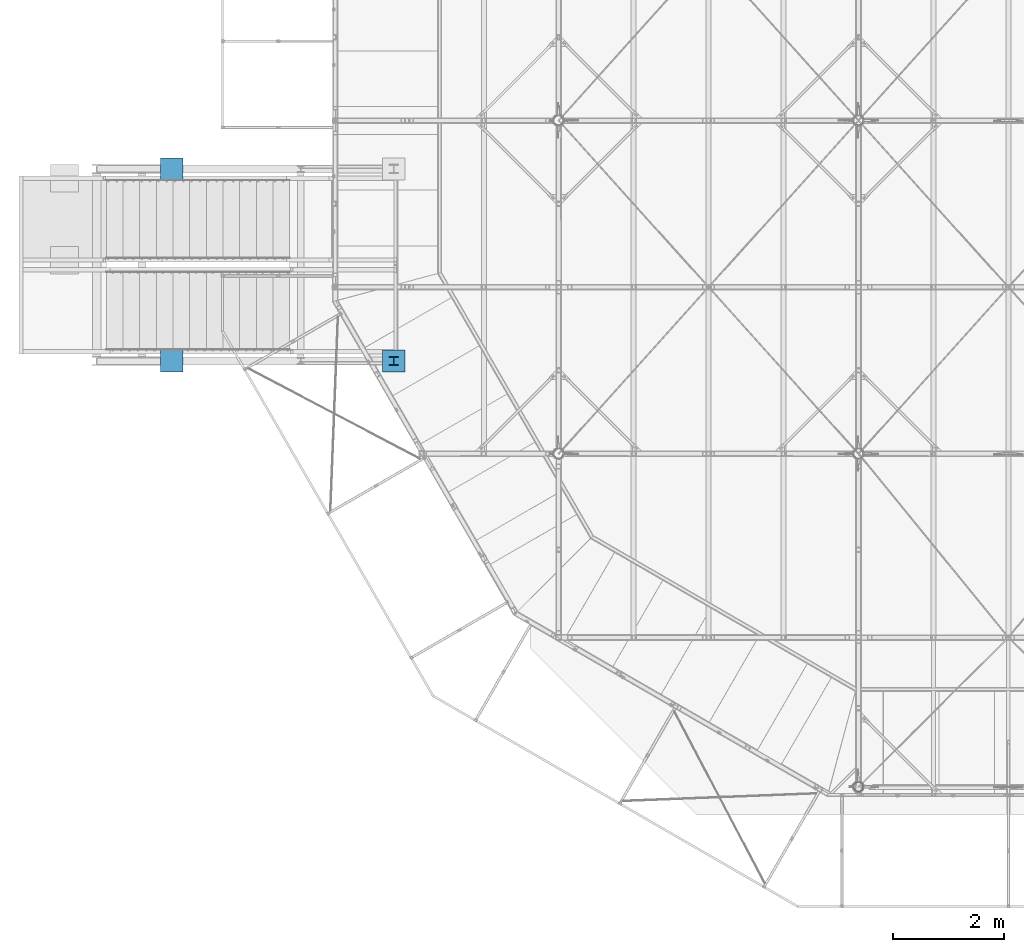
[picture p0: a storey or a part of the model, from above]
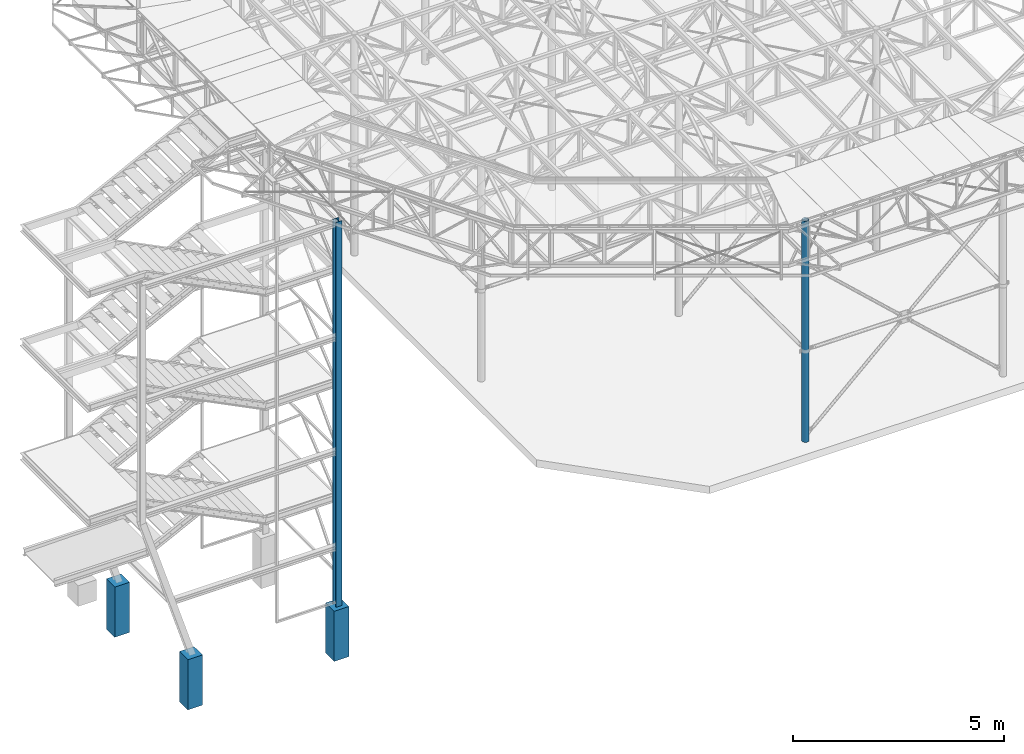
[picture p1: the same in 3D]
Properties of the parts of a building model (IFC2X3), part 1 of 2

# File
Description: ViewDefinition[CoordinationView_V2.0, QuantityTakeOffAddOnView], Option [BaseQuantities:On], Option [GridExport:On], Option [Assemblies:On], Option [Bolts:On], Option [Rebars:On], Option [PourObjects:Off], Option [Welds:Off], Option [SurfaceTreatments:Off], Option [LocationBy:0], Option [ViewColors:Off], Option [SectionedSpine:Off], Option [PropertySets:On], Option [Export all:On]
File name: IR_026-25_ifc_wzmocnienia_lądowiska.ifc
Time: 2025-10-02T10:39:26
Author: INFRARED\aneta.moskala
Organization: Structural Designer
Written by: IFC Database Version: Work
Made in: Tekla Structures Educational 2018, IFC Export Version: 4.0.0.0 Mar 15 2018

# IfcSite, Budowa
RefElevation: 0 mm

# IfcBuildingStorey, Undefined
In: Undefined
Elevation: 0 mm

# IfcBeam: BL8*100 (32)
In: Undefined
Description: BL8*100; Material: STEEL/S235JR
Tekla Common - Bottom elevation: +10.066; Top elevation: +10.166; Phase: 4; Class: 12
Tekla Quantity - Volume: 0 m3; Gross footprint area: 0 m2; Net surface area: 0.1 m2; Height: 100 mm; Width: 8 mm
Pset_BeamCommon - LoadBearing: no
Name | Weight (kg) | Area per tons (m2) | Tekla Quantity, Length (mm) | Reference | BaseQuantities, Length (mm) | OuterSurfaceArea (m2) | NetVolume (m3) | NetWeight (kg)
4 x BEAM | 3 | 35 | 479 | St10 | 479.039 | 0.104985 | 0.000382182 | 3.00013
12 x BEAM | 2.5 | 35.1 | 404 | s4 | 404.039 | 0.0887853 | 0.000322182 | 2.52913
6 x BEAM | 3.5 | 34.9 | 554 | s7 | 554.039 | 0.121185 | 0.000442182 | 3.47113
6 x BEAM | 3 | 35 | 479 | s5 | 479.039 | 0.104985 | 0.000382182 | 3.00013
4 x BEAM | 2.5 | 35.1 | 404 | St7 | 404.039 | 0.0887853 | 0.000322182 | 2.52913

# IfcBeam: C70*40*4 (34)
In: Undefined
Description: C70*40*4; Material: STEEL/S235
Tekla Common - Phase: 4; Class: 11
Tekla Quantity - Volume: 0 m3; Height: 70 mm; Width: 40 mm
Pset_BeamCommon - LoadBearing: no
Name | Bottom elevation | Top elevation | Weight (kg) | Gross footprint area (m2) | Area per tons (m2) | Net surface area (m2) | Tekla Quantity, Length (mm) | Reference | BaseQuantities, Length (mm) | OuterSurfaceArea (m2) | NetVolume (m3) | NetWeight (kg)
BEAM | +13.910 | +13.980 | 3.8 | 0 | 65.7 | 0.4 | 863 | k71 | 862.953 | 0.252133 | 0.000488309 | 3.83323
BEAM | +13.910 | +13.980 | 3.5 | 0 | 65.7 | 0.2 | 771.7 | k72 | 771.695 | 0.225485 | 0.000436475 | 3.42633
BEAM | +13.910 | +13.980 | 4.3 | 0 | 65.7 | 0.4 | 973 | k74 | 972.996 | 0.284266 | 0.000550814 | 4.32389
BEAM | +13.910 | +13.980 | 3.5 | 0 | 65.7 | 0.2 | 773 | k69 | 773.009 | 0.225869 | 0.000437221 | 3.43219
BEAM | +13.910 | +13.980 | 3.5 | 0 | 65.7 | 0.2 | 771.8 | k72 | 771.782 | 0.225511 | 0.000436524 | 3.42672
BEAM | +13.910 | +13.980 | 3.5 | 0 | 65.7 | 0.2 | 774.7 | k73 | 774.742 | 0.226375 | 0.000438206 | 3.43992
BEAM | +13.910 | +13.980 | 3.8 | 0 | 65.7 | 0.4 | 863 | k71 | 862.922 | 0.252124 | 0.000488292 | 3.83309
20 x BEAM | +13.910 | +13.980 | 13.2 | 0.1 | 65.7 | 0.8 | 2950 | K6 | 2950 | 0.862536 | 0.0016756 | 13.1535
2 x BEAM | +13.910 | +13.980 | 3.5 | 0 | 65.7 | 0.2 | 773 | k69 | 772.888 | 0.225834 | 0.000437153 | 3.43165
2 x BEAM | +13.910 | +13.980 | 3 | 0 | 65.9 | 0.2 | 683.7 | k70 | 683.709 | 0.199794 | 0.000386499 | 3.03402
BEAM | +13.911 | +13.981 | 12.1 | 0.1 | 65.7 | 0.8 | 2703.9 | K36 | 2703.9 | 0.790676 | 0.00153582 | 12.0562
BEAM | +13.910 | +13.980 | 6.8 | 0.1 | 65.7 | 0.4 | 1520 | K3 | 1520 | 0.444976 | 0.00086336 | 6.77738
BEAM | +13.910 | +13.980 | 6.7 | 0.1 | 65.7 | 0.4 | 1505 | K2 | 1505 | 0.440596 | 0.00085484 | 6.71049

# IfcBeam: CHS88.9*3 (23)
In: Undefined
Description: CHS88.9*3; Material: STEEL/S235JR
Tekla Common - Bottom elevation: +10.072; Top elevation: +10.160; Phase: 4; Class: 9
Tekla Quantity - Volume: 0 m3; Gross footprint area: 0 m2; Area per tons: 44.9 m2; Net surface area: 1.4 m2; Height: 88.9 mm; Width: 88.9 mm
Pset_BeamCommon - LoadBearing: no
Name | Weight (kg) | Tekla Quantity, Length (mm) | Reference | BaseQuantities, Length (mm) | OuterSurfaceArea (m2) | NetVolume (m3) | NetWeight (kg)
11 x BEAM | 30.2 | 4893.7 | s2 | 4893.73 | 1.35623 | 0.00384995 | 30.2221
12 x BEAM | 34.5 | 5584.2 | s6 | 5584.18 | 1.54783 | 0.00439468 | 34.4982

# IfcBeam: D10 (16)
In: Undefined
Description: D10; Material: STEEL/S235
Tekla Common - Top elevation: +13.951; Phase: 4; Class: 5
Tekla Quantity - Weight: 1.9 kg; Volume: 0 m3; Gross footprint area: 0 m2; Area per tons: 55.2 m2; Net surface area: 0.1 m2; Height: 10 mm; Width: 10 mm; Length: 3489 mm
Pset_BeamCommon - LoadBearing: no; Reference: B5
BaseQuantities - Length: 3489.02 mm; OuterSurfaceArea: 0.106957 m2; NetVolume: 0.000246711 m3; NetWeight: 1.93668 kg
Name | Bottom elevation
15 x BEAM | +13.848
BEAM | +13.847

# IfcBeam: D16 (32)
In: Undefined
Description: D16; Material: STEEL/S235
Tekla Common - Bottom elevation: +12.772; Top elevation: +12.788; Phase: 4; Class: 5
Tekla Quantity - Volume: 0 m3; Gross footprint area: 0 m2; Area per tons: 33 m2; Net surface area: 0.2 m2; Height: 16 mm; Width: 16 mm
Pset_BeamCommon - LoadBearing: no
Name | Weight (kg) | Tekla Quantity, Length (mm) | Reference | BaseQuantities, Length (mm) | OuterSurfaceArea (m2) | NetVolume (m3) | NetWeight (kg)
24 x BEAM | 6.1 | 4036.1 | K21 | 4036.09 | 0.20095 | 0.000774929 | 6.08319
4 x BEAM | 6.4 | 4271.5 | K27 | 4271.55 | 0.212651 | 0.000820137 | 6.43807
4 x BEAM | 5.7 | 3811.3 | K26 | 3811.31 | 0.189781 | 0.000731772 | 5.74441

# IfcBeam: HEB140, COLUMN
In: Undefined
Description: HEB140; Material: STEEL/S235
Tekla Common - Bottom elevation: +2.640; Top elevation: +2.780; Phase: 2; Class: 4
Tekla Quantity - Weight: 111.4 kg; Volume: 0 m3; Gross footprint area: 0.4 m2; Area per tons: 23.8 m2; Net surface area: 2.7 m2; Height: 140 mm; Width: 140 mm; Length: 3300 mm
Pset_BeamCommon - LoadBearing: no; Reference: S3
BaseQuantities - Length: 3300 mm; OuterSurfaceArea: 2.6565 m2; NetVolume: 0.0137676 m3; NetWeight: 108.076 kg

# IfcBeam: HEB160 (3)
In: Undefined
Description: HEB160; Material: STEEL/S235
Tekla Common - Phase: 2; Class: 4
Tekla Quantity - Weight: 140.7 kg; Volume: 0 m3; Gross footprint area: 0.4 m2; Area per tons: 21.5 m2; Net surface area: 3.1 m2; Height: 160 mm; Width: 160 mm; Length: 3300 mm
Pset_BeamCommon - LoadBearing: no; Reference: S2
BaseQuantities - Length: 3300 mm; OuterSurfaceArea: 3.0294 m2; NetVolume: 0.0172656 m3; NetWeight: 135.535 kg
Name | Bottom elevation | Top elevation
COLUMN | +11.990 | +12.150
COLUMN | +8.690 | +8.850
COLUMN | +5.390 | +5.550

# IfcBeam: IPE120 (6)
In: Undefined
Description: IPE120; Material: STEEL/S235
Tekla Common - Bottom elevation: +13.760; Top elevation: +13.880; Phase: 4; Class: 5
Tekla Quantity - Weight: 28.5 kg; Volume: 0 m3; Gross footprint area: 0.2 m2; Area per tons: 45.8 m2; Net surface area: 1.3 m2; Height: 120 mm; Width: 64 mm
Pset_BeamCommon - LoadBearing: no
Name | Tekla Quantity, Length (mm) = BaseQuantities, Length (mm) | Reference | OuterSurfaceArea (m2) | NetVolume (m3) | NetWeight (kg)
2 x BEAM | 2753.9 | B8 | 1.3081 | 0.00352213 | 27.6487
2 x BEAM | 2754.9 | B8 | 1.30858 | 0.00352341 | 27.6587
BEAM | 2753.9 | k79 | 1.3081 | 0.00352213 | 27.6487
BEAM | 2754.9 | k79 | 1.30858 | 0.00352341 | 27.6587

# IfcBeam: IPE180 (64)
In: Undefined
Description: IPE180; Material: STEEL/S235
Tekla Common - Bottom elevation: +13.700; Top elevation: +13.880; Phase: 4; Class: 5
Tekla Quantity - Volume: 0 m3; Gross footprint area: 0.4 m2; Area per tons: 37.2 m2; Height: 180 mm; Width: 91 mm
Pset_BeamCommon - LoadBearing: no
Name | Weight (kg) | Net surface area (m2) | Tekla Quantity, Length (mm) = BaseQuantities, Length (mm) | Reference | OuterSurfaceArea (m2) | NetVolume (m3) | NetWeight (kg)
46 x BEAM | 54.4 | 2.1 | 2900 | B6 | 2.0242 | 0.00674308 | 52.9332
9 x BEAM | 60.2 | 2.3 | 3210 | B7 | 2.24058 | 0.00746389 | 58.5916
9 x BEAM | 60.2 | 2.3 | 3211 | B7 | 2.24128 | 0.00746622 | 58.6098

# IfcBeam: L150*75*9, BEAM
In: Undefined
Description: L150*75*9; Material: STEEL/S235
Tekla Common - Bottom elevation: +13.880; Top elevation: +14.030; Phase: 4; Class: 5
Tekla Quantity - Weight: 84.4 kg; Volume: 0 m3; Gross footprint area: 0 m2; Area per tons: 28.8 m2; Net surface area: 2.4 m2; Height: 150 mm; Width: 75 mm; Length: 5511.2 mm
Pset_BeamCommon - LoadBearing: no; Reference: k82
BaseQuantities - Length: 5511.18 mm; OuterSurfaceArea: 2.43043 m2; NetVolume: 0.0106522 m3; NetWeight: 83.6199 kg

# IfcBeam: L60*40*6, BEAM
In: Undefined
Description: L60*40*6; Material: STEEL/S235
Tekla Common - Bottom elevation: +13.984; Top elevation: +14.024; Phase: 4; Class: 5
Tekla Quantity - Weight: 29.1 kg; Volume: 0 m3; Gross footprint area: 0 m2; Area per tons: 43.7 m2; Net surface area: 1.3 m2; Height: 60 mm; Width: 40 mm; Length: 6524.9 mm
Pset_BeamCommon - LoadBearing: no; Reference: k92
BaseQuantities - Length: 6524.86 mm; OuterSurfaceArea: 1.27235 m2; NetVolume: 0.0036739 m3; NetWeight: 28.8401 kg

# IfcBeam: RHS100*60*6 (2)
In: Undefined
Description: RHS100*60*6; Material: STEEL/S235
Tekla Common - Bottom elevation: +13.780; Top elevation: +13.880; Phase: 4; Class: 11
Tekla Quantity - Weight: 89.6 kg; Volume: 0 m3; Gross footprint area: 0.4 m2; Area per tons: 22.6 m2; Net surface area: 2 m2; Height: 100 mm; Width: 60 mm; Length: 6524 mm
Pset_BeamCommon - LoadBearing: no; Reference: k25
BaseQuantities - Length: 6524 mm; OuterSurfaceArea: 2.02768 m2; NetVolume: 0.011416 m3; NetWeight: 89.6155 kg

# IfcBeam: RHS60*40*6 (77)
In: Undefined
Description: RHS60*40*6; Material: STEEL/S235
Tekla Common - Bottom elevation: +13.880; Top elevation: +13.984; Phase: 4; Class: 5
Tekla Quantity - Weight: 0.8 kg; Volume: 0 m3; Gross footprint area: 0 m2; Area per tons: 25 m2; Net surface area: 0 m2; Height: 60 mm; Width: 40 mm
Pset_BeamCommon - LoadBearing: no; Reference: B4
Name | Tekla Quantity, Length (mm) | BaseQuantities, Length (mm) | OuterSurfaceArea (m2) | NetVolume (m3) | NetWeight (kg)
28 x BEAM | 103.6 | 103.598 | 0.0214324 | 0.000109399 | 0.858784
28 x BEAM | 104 | 103.989 | 0.0215089 | 0.000109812 | 0.862027
7 x BEAM | 104 | 103.986 | 0.0215084 | 0.000109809 | 0.862003
14 x BEAM | 104 | 103.938 | 0.021499 | 0.000109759 | 0.861604

# IfcBeam: SHS100*5 (4)
In: Undefined
Description: SHS100*5; Material: STEEL/S235
Tekla Common - Bottom elevation: +13.780; Top elevation: +13.880; Phase: 4; Class: 11
Tekla Quantity - Weight: 48.7 kg; Volume: 0 m3; Gross footprint area: 0.4 m2; Area per tons: 26.9 m2; Net surface area: 1.3 m2; Height: 100 mm; Width: 100 mm; Length: 3305.6 mm
Pset_BeamCommon - LoadBearing: no; Reference: k36
BaseQuantities - Length: 3305.58 mm; OuterSurfaceArea: 1.30752 m2; NetVolume: 0.0062003 m3; NetWeight: 48.6724 kg

# IfcBeam: SHS100*8 (51)
In: Undefined
Description: SHS100*8; Material: STEEL/S235
Tekla Quantity - Volume: 0 m3; Height: 100 mm; Width: 100 mm
Tekla Common - Bottom elevation: +13.780; Top elevation: +13.880; Phase: 4; Class: 11
Pset_BeamCommon - LoadBearing: no
Name | Weight (kg) | Gross footprint area (m2) | Area per tons (m2) | Net surface area (m2) | Tekla Quantity, Length (mm) | Reference | BaseQuantities, Length (mm) | OuterSurfaceArea (m2) | NetVolume (m3) | NetWeight (kg)
4 x BEAM | 67 | 0.4 | 17.4 | 1.3 | 2900 | k46 | 2900 | 1.1632 | 0.0085376 | 67.0202
4 x BEAM | 4.7 | 0 | 18 | 0.1 | 212.3 | k44 | 212.282 | 0.0828103 | 0.000585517 | 4.59631
4 x BEAM | 56.4 | 0.2 | 17.4 | 1 | 2448.9 | k23 | 2448.92 | 0.980265 | 0.00718892 | 56.433
4 x BEAM | 93 | 0.4 | 17.3 | 1.6 | 4025 | k22 | 4025 | 1.6132 | 0.0118496 | 93.0194
2 x BEAM | 92.3 | 0.4 | 17.3 | 1.6 | 4000.9 | k19 | 4000.92 | 1.60107 | 0.011758 | 92.3004
12 x BEAM | 122.5 | 0.4 | 17.3 | 2.1 | 5300 | k9 | 5300 | 2.1232 | 0.0156032 | 122.485
4 x BEAM | 75.8 | 0.4 | 17.4 | 1.3 | 3286 | k11 | 3286.02 | 1.31511 | 0.00965334 | 75.7787
8 x BEAM | 134.9 | 0.7 | 17.3 | 2.3 | 5852 | k6 | 5852.04 | 2.33901 | 0.017187 | 134.918
9 x BEAM | 121.1 | 0.4 | 17.3 | 2.1 | 5252 | k2 | 5252.04 | 2.09901 | 0.0154206 | 121.052

# IfcBeam: SHS50*5 (36)
In: Undefined
Description: SHS50*5; Material: STEEL/S235
Tekla Common - Bottom elevation: +12.805; Top elevation: +12.855; Phase: 4; Class: 11
Tekla Quantity - Weight: 12 kg; Volume: 0 m3; Gross footprint area: 0.1 m2; Area per tons: 28.5 m2; Net surface area: 0.4 m2; Height: 50 mm; Width: 50 mm
Pset_BeamCommon - LoadBearing: no; Reference: k48
Name | Tekla Quantity, Length (mm) | BaseQuantities, Length (mm) | OuterSurfaceArea (m2) | NetVolume (m3) | NetWeight (kg)
18 x BEAM | 1700.3 | 1700.3 | 0.34106 | 0.00153027 | 12.0126
18 x BEAM | 1700 | 1700.02 | 0.341004 | 0.00153002 | 12.0106

# IfcBeam: SHS60*4 (10)
In: Undefined
Description: SHS60*4; Material: STEEL/S235
Tekla Common - Phase: 2; Class: 4
Tekla Quantity - Volume: 0 m3; Area per tons: 34.2 m2; Height: 60 mm; Width: 60 mm
Pset_BeamCommon - LoadBearing: no
Name | Bottom elevation | Top elevation | Weight (kg) | Gross footprint area (m2) | Net surface area (m2) | Tekla Quantity, Length (mm) = BaseQuantities, Length (mm) | Reference | OuterSurfaceArea (m2) | NetVolume (m3) | NetWeight (kg)
2 x BEAM | +2.780 | +5.400 | 18.4 | 0 | 0.6 | 2620 | B1 | 0.62976 | 0.00234752 | 18.428
2 x BEAM | +8.840 | +12.000 | 22.2 | 0 | 0.8 | 3160 | B2 | 0.75936 | 0.00283136 | 22.2262
2 x BEAM | +5.540 | +8.700 | 22.2 | 0 | 0.8 | 3160 | B2 | 0.75936 | 0.00283136 | 22.2262
COLUMN | +12.040 | +12.100 | 23.2 | 0.2 | 0.8 | 3300 | k100 | 0.79296 | 0.0029568 | 23.2109
COLUMN | +8.740 | +8.800 | 23.2 | 0.2 | 0.8 | 3300 | k100 | 0.79296 | 0.0029568 | 23.2109
COLUMN | +5.440 | +5.500 | 23.2 | 0.2 | 0.8 | 3300 | k100 | 0.79296 | 0.0029568 | 23.2109
COLUMN | +1.880 | +1.940 | 23.2 | 0.2 | 0.8 | 3300 | S7 | 0.79296 | 0.0029568 | 23.2109

# IfcBeam: UPE200 (3)
In: Undefined
Description: UPE200; Material: STEEL/S235
Tekla Common - Phase: 2; Class: 4
Tekla Quantity - Weight: 81.6 kg; Volume: 0 m3; Gross footprint area: 0.4 m2; Area per tons: 27.9 m2; Net surface area: 2.3 m2; Height: 200 mm; Width: 80 mm; Length: 3300 mm
Pset_BeamCommon - LoadBearing: no; Reference: k99
BaseQuantities - Length: 3300 mm; OuterSurfaceArea: 2.277 m2; NetVolume: 0.0102135 m3; NetWeight: 80.176 kg
Name | Bottom elevation | Top elevation
COLUMN | +10.500 | +10.700
COLUMN | +7.200 | +7.400
COLUMN | +3.900 | +4.100

# IfcBeam: UPN200 (3)
In: Undefined
Description: UPN200; Material: STEEL/S235
Tekla Common - Phase: 2; Class: 3
Tekla Quantity - Weight: 80.9 kg; Volume: 0 m3; Gross footprint area: 0.2 m2; Area per tons: 26.1 m2; Net surface area: 2.2 m2; Height: 200 mm; Width: 75 mm; Length: 3200 mm
Pset_BeamCommon - LoadBearing: no; Reference: A1
BaseQuantities - Length: 3200 mm; OuterSurfaceArea: 2.112 m2; NetVolume: 0.0103344 m3; NetWeight: 81.125 kg
Name | Bottom elevation | Top elevation
BELKA | +12.150 | +12.350
BELKA | +8.850 | +9.050
BELKA | +5.550 | +5.750

# IfcColumn: 400*400 (4)
In: Undefined
Description: 400*400; Material: CONCRETE/C25/30
Tekla Common - Bottom elevation: -0.430; Top elevation: +1.020; Phase: 2; Class: 13
Tekla Quantity - Weight: 556.8 kg; Volume: 0.2 m3; Gross footprint area: 0.2 m2; Area per tons: 4.7 m2; Net surface area: 2.6 m2; Height: 400 mm; Width: 400 mm; Length: 1450 mm
Pset_ColumnCommon - LoadBearing: yes; Reference: S4
BaseQuantities - Length: 1450 mm; OuterSurfaceArea: 2.64 m2; NetVolume: 0.232 m3; NetWeight: 556.8 kg

# IfcColumn: 500*500 (2)
In: Undefined
Description: 500*500; Material: CONCRETE/C25/30
Tekla Common - Bottom elevation: +2.180; Top elevation: +2.780; Phase: 2; Class: 13
Tekla Quantity - Weight: 360 kg; Volume: 0.2 m3; Gross footprint area: 0.4 m2; Area per tons: 4.7 m2; Net surface area: 1.7 m2; Height: 500 mm; Width: 500 mm; Length: 600 mm
Pset_ColumnCommon - LoadBearing: yes; Reference: S1
BaseQuantities - Length: 600 mm; OuterSurfaceArea: 1.7 m2; NetVolume: 0.15 m3; NetWeight: 360 kg

# IfcColumn: CHS177.8*12.5 (16)
In: Undefined
Description: CHS177.8*12.5; Material: STEEL/S235
Tekla Common - Bottom elevation: +7.491; Top elevation: +13.880; Phase: 4; Class: 4
Tekla Quantity - Weight: 321.9 kg; Volume: 0 m3; Gross footprint area: 0 m2; Area per tons: 11.1 m2; Net surface area: 3.6 m2; Height: 177.8 mm; Width: 177.8 mm; Length: 6389 mm
Pset_ColumnCommon - LoadBearing: no
BaseQuantities - Length: 6389 mm; OuterSurfaceArea: 3.56546 m2; NetVolume: 0.0410009 m3; NetWeight: 321.857 kg
Name | Reference
14 x COLUMN | k1
2 x COLUMN | S12

# IfcColumn: HEB120, BEAM
In: Undefined
Description: HEB120; Material: STEEL/S235
Tekla Common - Bottom elevation: +12.140; Top elevation: +13.800; Phase: 2; Class: 4
Tekla Quantity - Weight: 44.3 kg; Volume: 0 m3; Gross footprint area: 0 m2; Area per tons: 25.7 m2; Net surface area: 1.3 m2; Height: 120 mm; Width: 120 mm; Length: 1660 mm
Pset_ColumnCommon - LoadBearing: no; Reference: k127
BaseQuantities - Length: 1660 mm; OuterSurfaceArea: 1.13876 m2; NetVolume: 0.00543982 m3; NetWeight: 42.7026 kg

# IfcColumn: HEB160 (2)
In: Undefined
Description: HEB160; Material: STEEL/S235
Tekla Common - Bottom elevation: +1.020; Top elevation: +12.140; Phase: 2; Class: 4
Tekla Quantity - Weight: 474 kg; Volume: 0.1 m3; Gross footprint area: 0 m2; Area per tons: 21.5 m2; Net surface area: 10.5 m2; Height: 160 mm; Width: 160 mm; Length: 11120 mm
Pset_ColumnCommon - LoadBearing: no; Reference: k96
BaseQuantities - Length: 11120 mm; OuterSurfaceArea: 10.2082 m2; NetVolume: 0.0581798 m3; NetWeight: 456.712 kg

# IfcDiscreteAccessory: ANGLE (146)
In: Undefined
Description: 3*40; Material: STEEL/S235JR
Tekla Common - Phase: 2; Class: 1
Tekla Quantity - Weight: 0.3 kg; Volume: 0 m3; Gross footprint area: 0 m2; Area per tons: 92.1 m2; Net surface area: 0 m2; Height: 3 mm; Width: 40 mm; Length: 300 mm
Pset_PlateCommon - LoadBearing: yes; Reference: bs2
BaseQuantities - NetArea: 0.02604 m2; GrossArea: 0.02604 m2; CrossSectionArea: 0.00012 m2; NetVolume: 0.000036 m3; GrossVolume: 0.000036 m3
Name | Bottom elevation | Top elevation
2 x ANGLE | +13.810 | +13.850
2 x ANGLE | +13.660 | +13.700
2 x ANGLE | +13.510 | +13.550
2 x ANGLE | +13.360 | +13.400
2 x ANGLE | +13.210 | +13.250
2 x ANGLE | +13.060 | +13.100
2 x ANGLE | +12.910 | +12.950
2 x ANGLE | +12.760 | +12.800
2 x ANGLE | +12.610 | +12.650
2 x ANGLE | +12.460 | +12.500
2 x ANGLE | +12.310 | +12.350
2 x ANGLE | +12.160 | +12.200
2 x ANGLE | +12.010 | +12.050
2 x ANGLE | +11.860 | +11.900
2 x ANGLE | +11.710 | +11.750
2 x ANGLE | +11.560 | +11.600
2 x ANGLE | +11.410 | +11.450
2 x ANGLE | +11.260 | +11.300
2 x ANGLE | +11.110 | +11.150
2 x ANGLE | +10.960 | +11.000
2 x ANGLE | +10.810 | +10.850
2 x ANGLE | +10.660 | +10.700
2 x ANGLE | +10.510 | +10.550
2 x ANGLE | +10.360 | +10.400
2 x ANGLE | +10.210 | +10.250
2 x ANGLE | +10.060 | +10.100
2 x ANGLE | +9.910 | +9.950
2 x ANGLE | +9.760 | +9.800
2 x ANGLE | +9.610 | +9.650
2 x ANGLE | +9.460 | +9.500
2 x ANGLE | +9.310 | +9.350
2 x ANGLE | +9.160 | +9.200
2 x ANGLE | +9.010 | +9.050
2 x ANGLE | +8.860 | +8.900
2 x ANGLE | +8.710 | +8.750
2 x ANGLE | +8.560 | +8.600
2 x ANGLE | +8.410 | +8.450
2 x ANGLE | +8.260 | +8.300
2 x ANGLE | +8.110 | +8.150
2 x ANGLE | +7.960 | +8.000
2 x ANGLE | +7.810 | +7.850
2 x ANGLE | +7.660 | +7.700
2 x ANGLE | +7.510 | +7.550
2 x ANGLE | +7.360 | +7.400
2 x ANGLE | +5.560 | +5.600
2 x ANGLE | +7.210 | +7.250
2 x ANGLE | +7.060 | +7.100
2 x ANGLE | +6.910 | +6.950
2 x ANGLE | +6.760 | +6.800
2 x ANGLE | +6.610 | +6.650
2 x ANGLE | +6.460 | +6.500
2 x ANGLE | +6.310 | +6.350
2 x ANGLE | +6.160 | +6.200
2 x ANGLE | +6.010 | +6.050
2 x ANGLE | +5.860 | +5.900
2 x ANGLE | +5.710 | +5.750
2 x ANGLE | +5.410 | +5.450
2 x ANGLE | +5.260 | +5.300
2 x ANGLE | +5.110 | +5.150
2 x ANGLE | +4.960 | +5.000
2 x ANGLE | +4.810 | +4.850
2 x ANGLE | +4.660 | +4.700
2 x ANGLE | +4.510 | +4.550
2 x ANGLE | +4.360 | +4.400
2 x ANGLE | +4.210 | +4.250
2 x ANGLE | +4.060 | +4.100
2 x ANGLE | +3.910 | +3.950
2 x ANGLE | +3.760 | +3.800
2 x ANGLE | +3.610 | +3.650
2 x ANGLE | +3.460 | +3.500
2 x ANGLE | +3.310 | +3.350
2 x ANGLE | +3.160 | +3.200
2 x ANGLE | +3.010 | +3.050

# IfcDiscreteAccessory: BACKINGBAR (2)
In: Undefined
Description: BL80*5; Material: MISCELLANEOUS/DUMMY
Tekla Common - Bottom elevation: +10.076; Top elevation: +10.156; Phase: 4; Class: 99
Tekla Quantity - Weight: 0 kg; Volume: 0 m3; Gross footprint area: 0 m2; Area per tons: 0 m2; Net surface area: 0.1 m2; Height: 80 mm; Width: 5.2 mm; Length: 573.5 mm
Pset_PlateCommon - LoadBearing: yes; Reference: P1
BaseQuantities - NetArea: 0.0979473 m2; GrossArea: 0.0978329 m2; CrossSectionArea: 0.0004 m2; NetVolume: 0.000226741 m3; GrossVolume: 0.000228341 m3

# IfcDiscreteAccessory: BEAM (672)
In: Undefined
Material: STEEL/S235
Tekla Quantity - Volume: 0 m3
Pset_PlateCommon - LoadBearing: no
Name | Description | Bottom elevation | Top elevation | Phase | Class | Weight (kg) | Gross footprint area (m2) | Area per tons (m2) | Net surface area (m2) | Height (mm) | Width (mm) | Length (mm) | Reference | NetArea (m2) | GrossArea (m2) | CrossSectionArea (m2) | NetVolume (m3) | GrossVolume (m3)
BEAM | SHS60*4 | +1.110 | +1.170 | 2 | 4 | 11.6 | 0.1 | 34.2 | 0.4 | 60 | 60 | 1700 | k133 | 0.397459 | 0.401959 | 0.00085095 | 0.00147832 | 0.00149632
2 x BEAM | SHS60*4 | +1.110 | +2.640 | 2 | 4 | 10.6 | 0 | 34.2 | 0.4 | 60 | 60 | 1530 | k131 | 0.361159 | 0.361159 | 0.00085095 | 0.001344 | 0.001344
BEAM | SHS60*4 | +1.110 | +1.170 | 2 | 4 | 11.6 | 0.1 | 34.2 | 0.4 | 60 | 60 | 1700 | k132 | 0.397459 | 0.401959 | 0.00085095 | 0.00147832 | 0.00149632
BEAM | HEB120 | +13.680 | +13.800 | 2 | 4 | 89.1 | 0.4 | 25.7 | 2.4 | 120 | 120 | 3340 | k128 | 2.29124 | 2.29124 | 0.0034 | 0.0109452 | 0.011356
BEAM | HEB120 | +12.140 | +13.800 | 2 | 4 | 44.3 | 0 | 25.7 | 1.3 | 120 | 120 | 1660 | k127 | 1.13876 | 1.13876 | 0.0034 | 0.00543982 | 0.005644
BEAM | L60*40*6 | +13.984 | +14.024 | 4 | 5 | 29.1 | 0 | 43.7 | 1.3 | 60 | 40 | 6524.8 | k92 | 1.27233 | 1.27233 | 0.000568 | 0.00367384 | 0.00370606
BEAM | L60*40*6 | +13.984 | +14.024 | 4 | 5 | 29.1 | 0 | 43.7 | 1.3 | 60 | 40 | 6524.8 | k92 | 1.27232 | 1.27232 | 0.000568 | 0.00367384 | 0.00370605
BEAM | L60*40*6 | +13.984 | +14.024 | 4 | 5 | 29.1 | 0 | 43.7 | 1.3 | 60 | 40 | 6524.5 | k92 | 1.27228 | 1.27228 | 0.000568 | 0.00367371 | 0.00370593
2 x BEAM | L60*40*6 | +13.984 | +14.024 | 4 | 5 | 29.1 | 0 | 43.7 | 1.3 | 60 | 40 | 6524.5 | k92 | 1.27226 | 1.27226 | 0.000568 | 0.00367364 | 0.00370585
BEAM | L60*40*6 | +13.984 | +14.024 | 4 | 5 | 29.1 | 0 | 43.7 | 1.3 | 60 | 40 | 6524.9 | k92 | 1.27235 | 1.27235 | 0.000568 | 0.00367392 | 0.00370614
BEAM | L60*40*6 | +13.984 | +14.024 | 4 | 5 | 29.1 | 0 | 43.7 | 1.3 | 60 | 40 | 6523.8 | k92 | 1.27213 | 1.27213 | 0.000568 | 0.00367329 | 0.0037055
BEAM | L60*40*6 | +13.984 | +14.024 | 4 | 5 | 29.1 | 0 | 43.7 | 1.3 | 60 | 40 | 6524.8 | k92 | 1.27232 | 1.27232 | 0.000568 | 0.00367382 | 0.00370604
BEAM | L60*40*6 | +13.984 | +14.024 | 4 | 5 | 29.1 | 0 | 43.7 | 1.3 | 60 | 40 | 6524.9 | k92 | 1.27236 | 1.27236 | 0.000568 | 0.00367395 | 0.00370617
BEAM | L60*40*6 | +13.984 | +14.024 | 4 | 5 | 0.6 | 0 | 43.7 | 0 | 60 | 40 | 158.3 | k94 | 0.030865 | 0.030865 | 0.000568 | 0.0000767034 | 0.0000899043
BEAM | L60*40*6 | +13.984 | +14.024 | 4 | 5 | 0.6 | 0 | 43.7 | 0 | 60 | 40 | 158.3 | k93 | 0.0308649 | 0.0308649 | 0.000568 | 0.000076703 | 0.000089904
BEAM | L60*40*6 | +13.984 | +14.024 | 4 | 5 | 29.1 | 0 | 43.7 | 1.3 | 60 | 40 | 6524 | k92 | 1.27218 | 1.27218 | 0.000568 | 0.00367342 | 0.00370563
8 x BEAM | L50*6 | +13.940 | +13.990 | 4 | 5 | 24.6 | 0.4 | 43.4 | 1.1 | 50 | 50 | 5502.6 | k87 | 1.06751 | 1.06751 | 0.000569 | 0.0030928 | 0.00313098
8 x BEAM | L150*75*9 | +13.880 | +14.030 | 4 | 5 | 84.4 | 0 | 28.8 | 2.4 | 150 | 75 | 5511.2 | k82 | 2.43043 | 2.43043 | 0.00195 | 0.0106522 | 0.0107468
BEAM | L50*6 | +13.940 | +13.990 | 4 | 5 | 24.6 | 0.4 | 43.4 | 1.1 | 50 | 50 | 5502.6 | k87 | 1.0675 | 1.0675 | 0.000569 | 0.0030928 | 0.00313098
BEAM | L50*6 | +13.940 | +13.990 | 4 | 5 | 22.6 | 0.4 | 43.4 | 1 | 50 | 50 | 5066.7 | k91 | 0.982941 | 0.982941 | 0.000569 | 0.0028475 | 0.00288296
BEAM | L50*6 | +13.940 | +13.990 | 4 | 5 | 9.7 | 0.1 | 43.4 | 0.4 | 50 | 50 | 2168.2 | k90 | 0.420641 | 0.420641 | 0.000569 | 0.00120816 | 0.00123373
BEAM | L50*6 | +13.940 | +13.990 | 4 | 5 | 9.7 | 0.1 | 43.4 | 0.4 | 50 | 50 | 2168.4 | k89 | 0.420663 | 0.420663 | 0.000569 | 0.00120822 | 0.0012338
BEAM | L50*6 | +13.940 | +13.990 | 4 | 5 | 22.6 | 0.4 | 43.4 | 1 | 50 | 50 | 5066.5 | k88 | 0.982896 | 0.982896 | 0.000569 | 0.00284737 | 0.00288282
BEAM | L150*75*9 | +13.880 | +14.030 | 4 | 5 | 33.3 | 0 | 28.8 | 1 | 150 | 75 | 2173.4 | k86 | 0.95849 | 0.95849 | 0.00195 | 0.00420727 | 0.00423822
BEAM | L150*75*9 | +13.880 | +14.030 | 4 | 5 | 33.3 | 0 | 28.8 | 1 | 150 | 75 | 2173.6 | k85 | 0.95854 | 0.95854 | 0.00195 | 0.00420749 | 0.00423844
BEAM | L150*75*9 | +13.880 | +14.030 | 4 | 5 | 77.7 | 0 | 28.8 | 2.3 | 150 | 75 | 5076.2 | k84 | 2.2386 | 2.2386 | 0.00195 | 0.00981945 | 0.00989857
BEAM | L150*75*9 | +13.880 | +14.030 | 4 | 5 | 77.7 | 0 | 28.8 | 2.3 | 150 | 75 | 5076 | k83 | 2.2385 | 2.2385 | 0.00195 | 0.009819 | 0.00989812
2 x BEAM | SHS50*5 | +12.804 | +13.760 | 4 | 5 | 9.2 | 0 | 28.5 | 0.4 | 50 | 50 | 1351.6 | k81 | 0.26173 | 0.26173 | 0.00082961 | 0.00117142 | 0.00117142
BEAM | C70*40*4 | +13.911 | +13.983 | 4 | 11 | 1.7 | 0 | 66.1 | 0.1 | 70 | 40 | 385.2 | k76 | 0.112563 | 0.112563 | 0.000584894 | 0.000216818 | 0.000216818
BEAM | C70*40*4 | +13.910 | +13.980 | 4 | 11 | 4.7 | 0 | 65.7 | 0.4 | 70 | 40 | 1048.1 | k75 | 0.306182 | 0.306182 | 0.000584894 | 0.000593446 | 0.000593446
2 x BEAM | C70*40*4 | +13.910 | +13.980 | 4 | 11 | 3.5 | 0 | 65.7 | 0.2 | 70 | 40 | 774.7 | k73 | 0.226375 | 0.226375 | 0.000584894 | 0.000438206 | 0.000438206
BEAM | C70*40*4 | +13.910 | +13.980 | 4 | 11 | 3.5 | 0 | 65.7 | 0.2 | 70 | 40 | 771.8 | k72 | 0.225511 | 0.225511 | 0.000584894 | 0.000436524 | 0.000436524
BEAM | C70*40*4 | +13.910 | +13.980 | 4 | 11 | 3.8 | 0 | 65.7 | 0.4 | 70 | 40 | 863.1 | k71 | 0.252162 | 0.252162 | 0.000584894 | 0.000488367 | 0.000488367
BEAM | C70*40*4 | +13.910 | +13.980 | 4 | 11 | 3.5 | 0 | 65.7 | 0.2 | 70 | 40 | 774.8 | k73 | 0.226379 | 0.226379 | 0.000584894 | 0.000438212 | 0.000438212
BEAM | C70*40*4 | +13.910 | +13.980 | 4 | 11 | 3.8 | 0 | 65.7 | 0.4 | 70 | 40 | 863 | k71 | 0.252133 | 0.252133 | 0.000584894 | 0.000488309 | 0.000488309
BEAM | C70*40*4 | +13.910 | +13.980 | 4 | 11 | 3.5 | 0 | 65.7 | 0.2 | 70 | 40 | 773 | k69 | 0.225869 | 0.225869 | 0.000584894 | 0.000437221 | 0.000437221
BEAM | C70*40*4 | +13.910 | +13.980 | 4 | 11 | 3.5 | 0 | 65.7 | 0.2 | 70 | 40 | 771.8 | k72 | 0.225519 | 0.225519 | 0.000584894 | 0.000436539 | 0.000436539
2 x BEAM | C70*40*4 | +13.910 | +13.980 | 4 | 11 | 3 | 0 | 65.9 | 0.2 | 70 | 40 | 683.7 | k70 | 0.199794 | 0.199794 | 0.000584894 | 0.000386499 | 0.000386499
2 x BEAM | C70*40*4 | +13.910 | +13.980 | 4 | 11 | 3.5 | 0 | 65.7 | 0.2 | 70 | 40 | 773 | k69 | 0.225834 | 0.225834 | 0.000584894 | 0.000437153 | 0.000437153
BEAM | SHS50*4 | +13.830 | +13.981 | 4 | 11 | 0.6 | 0 | 36.3 | 0 | 50 | 50 | 150 | k55 | 0.0227267 | 0.0227267 | 0.00069095 | 0.0000797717 | 0.0000797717
BEAM | SHS50*4 | +13.916 | +13.981 | 4 | 11 | 1.5 | 0 | 35.3 | 0.1 | 50 | 50 | 296.9 | k64 | 0.0541961 | 0.409296 | 0.00069095 | 0.000195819 | 0.00150255
37 x BEAM | SHS50*4 | +13.335 | +13.880 | 4 | 11 | 3.1 | 0 | 34.9 | 0.1 | 50 | 50 | 544.7 | k57 | 0.106916 | 0.106916 | 0.00069095 | 0.000390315 | 0.000390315
BEAM | SHS50*4 | +13.830 | +13.966 | 4 | 11 | 9.9 | 0 | 34.7 | 0.4 | 50 | 50 | 1720.7 | k62 | 0.343794 | 0.40155 | 0.00069095 | 0.0012622 | 0.00147476
BEAM | SHS50*4 | +13.832 | +13.982 | 4 | 11 | 0.6 | 0 | 36.3 | 0 | 50 | 50 | 150 | k55 | 0.0227267 | 0.0227267 | 0.00069095 | 0.0000797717 | 0.0000797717
BEAM | SHS50*4 | +13.848 | +13.982 | 4 | 11 | 9 | 0 | 34.9 | 0.4 | 50 | 50 | 1678.6 | k59 | 0.313661 | 0.313661 | 0.00069095 | 0.00114644 | 0.00114644
BEAM | SHS50*4 | +12.982 | +13.863 | 4 | 11 | 10.1 | 0 | 34.9 | 0.4 | 50 | 50 | 1877.8 | k58 | 0.351218 | 0.351218 | 0.00069095 | 0.00128438 | 0.00128438
36 x BEAM | SHS50*4 | +13.830 | +13.980 | 4 | 11 | 0.6 | 0 | 36.3 | 0 | 50 | 50 | 150 | k55 | 0.0227703 | 0.0227703 | 0.00069095 | 0.0000799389 | 0.0000799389
36 x BEAM | SHS50*4 | +13.830 | +13.980 | 4 | 11 | 11.4 | 0 | 34.7 | 0.4 | 50 | 50 | 2005.1 | k54 | 0.396494 | 0.396494 | 0.00069095 | 0.00145549 | 0.00145549
8 x BEAM | RHS80*40*4 | +12.880 | +13.780 | 4 | 11 | 10.8 | 0 | 33.1 | 0.4 | 80 | 40 | 1553.2 | k47 | 0.358782 | 0.358782 | 0.000888 | 0.00134832 | 0.00137921
24 x BEAM | SHS90*4 | +12.880 | +13.780 | 4 | 11 | 9.7 | 0 | 33.5 | 0.4 | 89.9 | 90 | 900 | k31 | 0.32544 | 0.32544 | 0.00133095 | 0.0012384 | 0.0012384
4 x BEAM | SHS100*8 | +12.780 | +12.880 | 4 | 11 | 67 | 0.4 | 17.4 | 1.3 | 100 | 100 | 2900 | k46 | 1.1632 | 1.1632 | 0.0027638 | 0.0085376 | 0.0085376
8 x BEAM | RHS80*40*4 | +12.880 | +13.780 | 4 | 11 | 11.4 | 0 | 33.1 | 0.4 | 80 | 40 | 1640.9 | k45 | 0.379054 | 0.379054 | 0.000888 | 0.00142214 | 0.00145714
4 x BEAM | SHS100*8 | +12.780 | +12.880 | 4 | 11 | 72.1 | 0.4 | 17.4 | 1.3 | 100 | 100 | 3161.2 | k43 | 1.2511 | 1.2511 | 0.0027638 | 0.00918228 | 0.00918228
4 x BEAM | SHS100*8 | +12.780 | +12.880 | 4 | 11 | 4.7 | 0 | 18 | 0.1 | 100 | 100 | 212.3 | k44 | 0.0828103 | 0.0828103 | 0.0027638 | 0.000585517 | 0.000585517
4 x BEAM | SHS100*8 | +13.780 | +13.880 | 4 | 11 | 72.1 | 0.4 | 17.4 | 1.3 | 100 | 100 | 3161.2 | k43 | 1.2511 | 1.2511 | 0.0027638 | 0.00918228 | 0.00918228
4 x BEAM | RHS80*40*4 | +12.880 | +13.780 | 4 | 11 | 8.4 | 0 | 33.1 | 0.4 | 80 | 40 | 1199.1 | k41 | 0.277001 | 0.277001 | 0.000888 | 0.0010449 | 0.00106483
4 x BEAM | RHS80*40*4 | +12.880 | +13.780 | 4 | 11 | 8.2 | 0 | 33.1 | 0.4 | 80 | 40 | 1176.8 | k40 | 0.271838 | 0.271838 | 0.000888 | 0.00102416 | 0.00104499
4 x BEAM | RHS80*40*4 | +12.880 | +13.780 | 4 | 11 | 9.2 | 0 | 33.1 | 0.4 | 80 | 40 | 1330.6 | k39 | 0.307358 | 0.307358 | 0.000888 | 0.00116447 | 0.00118153
2 x BEAM | RHS80*40*4 | +12.880 | +13.780 | 4 | 11 | 9.5 | 0 | 33.1 | 0.4 | 80 | 40 | 1367.9 | k38 | 0.315981 | 0.315981 | 0.000888 | 0.00116258 | 0.00121468
12 x BEAM | SHS100*4 | +12.880 | +13.780 | 4 | 11 | 10.8 | 0 | 33.3 | 0.4 | 100 | 100 | 900 | k37 | 0.3616 | 0.3616 | 0.00149095 | 0.0013824 | 0.0013824
4 x BEAM | SHS100*5 | +12.780 | +12.880 | 4 | 11 | 48.7 | 0.4 | 26.9 | 1.3 | 100 | 100 | 3305.6 | k36 | 1.30752 | 1.342 | 0.00182961 | 0.0062003 | 0.00636484
4 x BEAM | SHS100*5 | +12.780 | +12.880 | 4 | 11 | 12.5 | 0.1 | 26.9 | 0.4 | 100 | 100 | 880.7 | k35 | 0.337562 | 0.350346 | 0.00182961 | 0.00159302 | 0.00165448
4 x BEAM | SHS100*5 | +13.780 | +13.880 | 4 | 11 | 12.5 | 0.1 | 26.9 | 0.4 | 100 | 100 | 880.7 | k35 | 0.337562 | 0.350346 | 0.00182961 | 0.00159302 | 0.00165448
2 x BEAM | RHS80*40*4 | +12.880 | +13.780 | 4 | 11 | 9.5 | 0 | 33.1 | 0.4 | 80 | 40 | 1367.9 | k42 | 0.315981 | 0.315981 | 0.000888 | 0.00116258 | 0.00121468
4 x BEAM | SHS50*4 | +12.805 | +12.855 | 4 | 11 | 3.5 | 0 | 34.9 | 0.1 | 50 | 50 | 636.1 | k30 | 0.121446 | 0.123885 | 0.00069095 | 0.000443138 | 0.000451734
4 x BEAM | SHS50*4 | +13.805 | +13.855 | 4 | 11 | 3.5 | 0 | 34.9 | 0.1 | 50 | 50 | 636.1 | k30 | 0.121446 | 0.123885 | 0.00069095 | 0.000443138 | 0.000451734
4 x BEAM | RHS80*40*4 | +12.880 | +13.780 | 4 | 11 | 8.8 | 0 | 33.1 | 0.4 | 80 | 40 | 1256.6 | k34 | 0.290281 | 0.290281 | 0.000888 | 0.00109552 | 0.00111588
4 x BEAM | RHS80*40*4 | +12.880 | +13.780 | 4 | 11 | 9.7 | 0 | 33.1 | 0.4 | 80 | 40 | 1411.9 | k33 | 0.326146 | 0.326146 | 0.000888 | 0.00123358 | 0.00125375
8 x BEAM | RHS80*40*4 | +12.880 | +13.780 | 4 | 11 | 11.6 | 0 | 33.1 | 0.4 | 80 | 40 | 1672.4 | k32 | 0.386329 | 0.386329 | 0.000888 | 0.0014518 | 0.00148511
4 x BEAM | SHS100*5 | +12.780 | +12.880 | 4 | 11 | 83.1 | 0.7 | 26.9 | 2.2 | 100 | 100 | 5683.4 | k29 | 2.23119 | 2.26901 | 0.00182961 | 0.0105833 | 0.0107677
4 x BEAM | SHS100*5 | +13.780 | +13.880 | 4 | 11 | 83.1 | 0.7 | 26.9 | 2.2 | 100 | 100 | 5683.4 | k29 | 2.23119 | 2.26901 | 0.00182961 | 0.0105833 | 0.0107677
BEAM | RHS50*30*5 | +12.880 | +13.842 | 4 | 11 | 8.8 | 0 | 28.5 | 0.2 | 50 | 30 | 1616.3 | k28 | 0.249313 | 0.249313 | 0.00062961 | 0.00111722 | 0.00111722
7 x BEAM | RHS50*30*5 | +12.880 | +13.780 | 4 | 11 | 8.2 | 0 | 28.5 | 0.2 | 50 | 30 | 1552.5 | k27 | 0.236511 | 0.236511 | 0.00062961 | 0.00105842 | 0.00105842
10 x BEAM | SHS50*5 | +12.880 | +13.780 | 4 | 11 | 6.4 | 0 | 28.5 | 0.2 | 50 | 50 | 900 | k26 | 0.181 | 0.181 | 0.00082961 | 0.00081 | 0.00081
2 x BEAM | RHS100*60*6 | +12.780 | +12.880 | 4 | 11 | 89.6 | 0.4 | 22.6 | 2 | 100 | 60 | 6524 | k25 | 2.02768 | 2.02768 | 0.00167464 | 0.011416 | 0.011416
10 x BEAM | RHS90*50*5 | +12.880 | +13.780 | 4 | 11 | 14.7 | 0 | 26.6 | 0.4 | 89.9 | 50 | 1453.4 | k5 | 0.390977 | 0.390977 | 0.00129 | 0.00182213 | 0.00187495
4 x BEAM | RHS90*50*5 | +12.880 | +13.780 | 4 | 11 | 13.8 | 0 | 26.6 | 0.4 | 89.9 | 50 | 1367 | k24 | 0.367725 | 0.367725 | 0.00129 | 0.00172579 | 0.00176344
119 x BEAM | SHS90*6 | +12.880 | +13.780 | 4 | 11 | 14.2 | 0 | 22.9 | 0.4 | 89.9 | 90 | 900 | k3 | 0.32616 | 0.32616 | 0.00191464 | 0.0018144 | 0.0018144
14 x BEAM | SHS100*8 | +12.880 | +13.780 | 4 | 11 | 20.8 | 0 | 17.4 | 0.4 | 100 | 100 | 900 | k12 | 0.3632 | 0.3632 | 0.0027638 | 0.0026496 | 0.0026496
4 x BEAM | SHS100*8 | +12.780 | +12.880 | 4 | 11 | 56.4 | 0.2 | 17.4 | 1 | 100 | 100 | 2448.9 | k23 | 0.980265 | 1.01236 | 0.0027638 | 0.00718892 | 0.00742742
6 x BEAM | RHS90*50*5 | +12.880 | +13.780 | 4 | 11 | 15.9 | 0 | 26.6 | 0.4 | 89.9 | 50 | 1573.5 | k21 | 0.42327 | 0.42327 | 0.00129 | 0.00197826 | 0.00202981
6 x BEAM | RHS90*50*5 | +12.880 | +13.780 | 4 | 11 | 15.2 | 0 | 26.6 | 0.4 | 89.9 | 50 | 1499.9 | k20 | 0.40346 | 0.40346 | 0.00129 | 0.00189017 | 0.00193481
4 x BEAM | SHS100*8 | +12.780 | +12.880 | 4 | 11 | 93 | 0.4 | 17.3 | 1.6 | 100 | 100 | 4025 | k22 | 1.6132 | 1.6132 | 0.0027638 | 0.0118496 | 0.0118496
2 x BEAM | SHS100*8 | +12.780 | +12.880 | 4 | 11 | 92.3 | 0.4 | 17.3 | 1.6 | 100 | 100 | 4000.9 | k19 | 1.60107 | 1.63316 | 0.0027638 | 0.011758 | 0.0119965
42 x BEAM | RHS90*50*5 | +12.880 | +13.780 | 4 | 11 | 14.7 | 0 | 26.6 | 0.4 | 89.9 | 50 | 1454.2 | k5 | 0.391182 | 0.391182 | 0.00129 | 0.00182306 | 0.00187593
42 x BEAM | RHS90*50*5 | +12.880 | +13.780 | 4 | 11 | 15.7 | 0 | 26.6 | 0.4 | 89.9 | 50 | 1548.2 | k4 | 0.416462 | 0.416462 | 0.00129 | 0.00194759 | 0.00199716
12 x BEAM | SHS100*8 | +12.780 | +12.880 | 4 | 11 | 122.5 | 0.4 | 17.3 | 2.1 | 100 | 100 | 5300 | k9 | 2.1232 | 2.1232 | 0.0027638 | 0.0156032 | 0.0156032
4 x BEAM | RHS90*50*5 | +12.880 | +13.780 | 4 | 11 | 17.7 | 0 | 26.6 | 0.4 | 89.9 | 50 | 1751.1 | k14 | 0.471054 | 0.471054 | 0.00129 | 0.0021857 | 0.00225896
4 x BEAM | RHS90*50*5 | +12.880 | +13.780 | 4 | 11 | 17.7 | 0 | 26.6 | 0.4 | 89.9 | 50 | 1737 | k13 | 0.467255 | 0.467255 | 0.00129 | 0.00217914 | 0.00224074
4 x BEAM | SHS100*8 | +12.780 | +12.880 | 4 | 11 | 75.8 | 0.4 | 17.4 | 1.3 | 100 | 100 | 3286 | k11 | 1.31511 | 1.3472 | 0.0027638 | 0.00965334 | 0.00989184
4 x BEAM | RHS90*50*5 | +12.880 | +13.780 | 4 | 11 | 15.2 | 0 | 26.6 | 0.4 | 89.9 | 50 | 1501.1 | k18 | 0.403801 | 0.403801 | 0.00129 | 0.00188028 | 0.00193644
4 x BEAM | RHS90*50*5 | +12.880 | +13.780 | 4 | 11 | 17.7 | 0 | 26.6 | 0.4 | 89.9 | 50 | 1751.9 | k17 | 0.471264 | 0.471264 | 0.00129 | 0.00218439 | 0.00225996
4 x BEAM | RHS90*50*5 | +12.880 | +13.780 | 4 | 11 | 15 | 0 | 26.6 | 0.4 | 89.9 | 50 | 1483.9 | k16 | 0.399162 | 0.399162 | 0.00129 | 0.00186927 | 0.00191419
4 x BEAM | RHS90*50*5 | +12.880 | +13.780 | 4 | 11 | 17.7 | 0 | 26.6 | 0.4 | 89.9 | 50 | 1741.2 | k15 | 0.468381 | 0.468381 | 0.00129 | 0.0021801 | 0.00224614
12 x BEAM | SHS100*8 | +12.780 | +12.880 | 4 | 11 | 134.9 | 0.7 | 17.3 | 2.3 | 100 | 100 | 5852 | k6 | 2.33901 | 2.4032 | 0.0027638 | 0.017187 | 0.017664
4 x BEAM | SHS100*8 | +13.780 | +13.880 | 4 | 11 | 139.4 | 0.7 | 17.3 | 2.4 | 100 | 100 | 6040.9 | k10 | 2.41707 | 2.44916 | 0.0027638 | 0.0177638 | 0.0180023
8 x BEAM | RHS90*50*5 | +12.880 | +13.780 | 4 | 11 | 16.4 | 0 | 26.6 | 0.4 | 89.9 | 50 | 1620.7 | k8 | 0.435959 | 0.435959 | 0.00129 | 0.00202554 | 0.00209066
8 x BEAM | RHS90*50*5 | +12.880 | +13.780 | 4 | 11 | 16.4 | 0 | 26.6 | 0.4 | 89.9 | 50 | 1620.8 | k8 | 0.436003 | 0.436003 | 0.00129 | 0.00202566 | 0.00209087
16 x BEAM | RHS90*50*5 | +12.880 | +13.780 | 4 | 11 | 16.9 | 0 | 26.6 | 0.4 | 89.9 | 50 | 1672.4 | k7 | 0.449881 | 0.449881 | 0.00129 | 0.00209758 | 0.00215742
9 x BEAM | SHS100*8 | +12.780 | +12.880 | 4 | 11 | 121.1 | 0.4 | 17.3 | 2.1 | 100 | 100 | 5252 | k2 | 2.09901 | 2.1632 | 0.0027638 | 0.0154206 | 0.0158976

# IfcDiscreteAccessory: BELKA (28)
In: Undefined
Description: UPN200; Material: STEEL/S235
Tekla Common - Phase: 2; Class: 3
Tekla Quantity - Volume: 0 m3; Area per tons: 26.1 m2; Height: 200 mm; Width: 75 mm
Pset_PlateCommon - LoadBearing: yes
BaseQuantities - CrossSectionArea: 0.00322 m2
Name | Bottom elevation | Top elevation | Weight (kg) | Gross footprint area (m2) | Net surface area (m2) | Length (mm) | Reference | NetArea (m2) = GrossArea (m2) | NetVolume (m3) | GrossVolume (m3)
BELKA | +13.800 | +14.000 | 19.5 | 0.1 | 0.4 | 770 | k126 | 0.5082 | 0.00241048 | 0.0024794
BELKA | +13.800 | +14.000 | 19.5 | 0.1 | 0.4 | 770 | k125 | 0.5082 | 0.00241048 | 0.0024794
BELKA | +12.150 | +12.350 | 37.6 | 0.1 | 1 | 1487.2 | k124 | 0.981561 | 0.00472672 | 0.00478883
BELKA | +12.150 | +12.350 | 37.6 | 0.1 | 1 | 1487.2 | k123 | 0.981561 | 0.00472672 | 0.00478883
BELKA | +12.150 | +12.350 | 39.4 | 0.1 | 1.1 | 1560 | k120 | 1.0296 | 0.00496178 | 0.0050232
BELKA | +12.150 | +12.350 | 39.4 | 0.1 | 1.1 | 1560 | k119 | 1.0296 | 0.00496178 | 0.0050232
BELKA | +10.500 | +10.700 | 47.1 | 0.1 | 1.3 | 1862.2 | k118 | 1.22906 | 0.00593778 | 0.00599633
BELKA | +10.500 | +10.700 | 47.1 | 0.1 | 1.3 | 1862.2 | k117 | 1.22906 | 0.00593778 | 0.00599633
BELKA | +10.500 | +10.700 | 48.9 | 0.1 | 1.3 | 1935 | k114 | 1.2771 | 0.00617284 | 0.0062307
BELKA | +10.500 | +10.700 | 48.9 | 0.1 | 1.3 | 1935 | k113 | 1.2771 | 0.00617284 | 0.0062307
BELKA | +8.850 | +9.050 | 37.6 | 0.1 | 1 | 1487.2 | k124 | 0.981561 | 0.00472672 | 0.00478883
BELKA | +8.850 | +9.050 | 37.6 | 0.1 | 1 | 1487.2 | k123 | 0.981561 | 0.00472672 | 0.00478883
BELKA | +8.850 | +9.050 | 39.4 | 0.1 | 1.1 | 1560 | k120 | 1.0296 | 0.00496178 | 0.0050232
BELKA | +8.850 | +9.050 | 39.4 | 0.1 | 1.1 | 1560 | k119 | 1.0296 | 0.00496178 | 0.0050232
BELKA | +7.200 | +7.400 | 47.1 | 0.1 | 1.3 | 1862.2 | k118 | 1.22906 | 0.00593778 | 0.00599633
BELKA | +7.200 | +7.400 | 47.1 | 0.1 | 1.3 | 1862.2 | k117 | 1.22906 | 0.00593778 | 0.00599633
BELKA | +7.200 | +7.400 | 48.9 | 0.1 | 1.3 | 1935 | k114 | 1.2771 | 0.00617284 | 0.0062307
BELKA | +7.200 | +7.400 | 48.9 | 0.1 | 1.3 | 1935 | k113 | 1.2771 | 0.00617284 | 0.0062307
BELKA | +5.550 | +5.750 | 37.6 | 0.1 | 1 | 1487.2 | k124 | 0.981561 | 0.00472672 | 0.00478883
BELKA | +5.550 | +5.750 | 37.6 | 0.1 | 1 | 1487.2 | k123 | 0.981561 | 0.00472672 | 0.00478883
BELKA | +5.550 | +5.750 | 39.4 | 0.1 | 1.1 | 1560 | k120 | 1.0296 | 0.00496178 | 0.0050232
BELKA | +5.550 | +5.750 | 39.4 | 0.1 | 1.1 | 1560 | k119 | 1.0296 | 0.00496178 | 0.0050232
BELKA | +3.900 | +4.100 | 47.1 | 0.1 | 1.3 | 1862.2 | k118 | 1.22906 | 0.00593778 | 0.00599633
BELKA | +3.900 | +4.100 | 47.1 | 0.1 | 1.3 | 1862.2 | k117 | 1.22906 | 0.00593778 | 0.00599633
BELKA | +3.900 | +4.100 | 48.9 | 0.1 | 1.3 | 1935 | k114 | 1.2771 | 0.00617284 | 0.0062307
BELKA | +3.900 | +4.100 | 48.9 | 0.1 | 1.3 | 1935 | k113 | 1.2771 | 0.00617284 | 0.0062307
BELKA | +2.780 | +2.980 | 64.4 | 0.2 | 1.7 | 2547.2 | k112 | 1.68116 | 0.00814999 | 0.00820203
BELKA | +2.780 | +2.980 | 64.4 | 0.2 | 1.7 | 2547.2 | k111 | 1.68116 | 0.00814999 | 0.00820203

# IfcDiscreteAccessory: BLACHA (424)
In: Undefined
Material: STEEL/S235
Tekla Common - Phase: 4; Class: 99
Tekla Quantity - Volume: 0 m3; Gross footprint area: 0 m2
Pset_PlateCommon - LoadBearing: yes
Name | Description | Bottom elevation | Top elevation | Weight (kg) | Area per tons (m2) | Net surface area (m2) | Height (mm) | Width (mm) | Length (mm) | Reference | NetArea (m2) | GrossArea (m2) | CrossSectionArea (m2) | NetVolume (m3) | GrossVolume (m3)
5 x BLACHA | BL8*126 | +12.407 | +12.610 | 1 | 36.3 | 0 | 126 | 8 | 203 | b18 | 0.035664 | 0.025578 | 0.000064 | 0.000125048 | 0.000125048
5 x BLACHA | BL8*126 | +12.407 | +12.610 | 1 | 36.3 | 0 | 126 | 8 | 203 | b18 | 0.0356643 | 0.0255781 | 0.000064 | 0.000125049 | 0.000125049
10 x BLACHA | BL8*86 | +9.874 | +10.053 | 1 | 36.1 | 0 | 86 | 8 | 190 | b17 | 0.0361085 | 0.01634 | 0.000064 | 0.00012752 | 0.00012752
5 x BLACHA | BL8*133 | +9.939 | +10.072 | 2.8 | 34.5 | 0.1 | 132.9 | 8 | 372.8 | b24 | 0.0973726 | 0.0495513 | 0.000064 | 0.000359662 | 0.000359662
10 x BLACHA | BL8*86 | +10.179 | +10.358 | 1 | 36.1 | 0 | 86 | 8 | 190 | b17 | 0.0361085 | 0.01634 | 0.000064 | 0.00012752 | 0.00012752
5 x BLACHA | BL8*133 | +10.160 | +10.293 | 2.8 | 34.5 | 0.1 | 132.9 | 8 | 372.8 | b24 | 0.0973726 | 0.0495513 | 0.000064 | 0.000359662 | 0.000359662
5 x BLACHA | BL8*126 | +7.622 | +7.825 | 1 | 36.3 | 0 | 126 | 8 | 203 | b18 | 0.0356639 | 0.025578 | 0.000064 | 0.000125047 | 0.000125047
5 x BLACHA | BL8*126 | +7.622 | +7.825 | 1 | 36.3 | 0 | 126 | 8 | 203 | b18 | 0.0356643 | 0.0255781 | 0.000064 | 0.000125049 | 0.000125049
10 x BLACHA | BL8*86 | +7.717 | +7.895 | 1 | 36.1 | 0 | 86 | 8 | 190 | b17 | 0.0361085 | 0.037096 | 0.000688 | 0.00012752 | 0.00013072
10 x BLACHA | BL8*86 | +12.337 | +12.515 | 1 | 36.1 | 0 | 86 | 8 | 190 | b17 | 0.0361085 | 0.037096 | 0.000688 | 0.00012752 | 0.00013072
43 x BLACHA | BL8*100 | +10.066 | +10.166 | 1.1 | 35.8 | 0 | 100 | 8 | 180 | b22 | 0.04048 | 0.04048 | 0.0008 | 0.000144 | 0.000144
24 x BLACHA | BL8*90 | +10.066 | +10.166 | 0.6 | 37.2 | 0 | 89.9 | 8 | 100 | b23 | 0.021021 | 0.00899123 | 0.000064 | 0.0000719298 | 0.0000719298
3 x BLACHA | BL8*100 | +10.066 | +10.166 | 1.1 | 35.8 | 0 | 100 | 8 | 180 | b26 | 0.04048 | 0.04048 | 0.0008 | 0.000144 | 0.000144
8 x BLACHA | BL8*86 | +9.880 | +10.055 | 1 | 36.1 | 0 | 86 | 8 | 190 | b17 | 0.0361085 | 0.01634 | 0.000064 | 0.00012752 | 0.00012752
8 x BLACHA | BL8*86 | +10.177 | +10.352 | 1 | 36.1 | 0 | 86 | 8 | 190 | b17 | 0.0361085 | 0.01634 | 0.000064 | 0.00012752 | 0.00012752
4 x BLACHA | BL8*133 | +9.940 | +10.072 | 3 | 34.4 | 0.1 | 132.5 | 8 | 396.5 | b27 | 0.103846 | 0.0525349 | 0.000064 | 0.000384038 | 0.000384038
4 x BLACHA | BL8*133 | +10.160 | +10.292 | 3 | 34.4 | 0.1 | 132.5 | 8 | 396.5 | b27 | 0.103846 | 0.0525351 | 0.000064 | 0.000384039 | 0.000384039
8 x BLACHA | BL8*86 | +7.703 | +7.878 | 1 | 36.1 | 0 | 86 | 8 | 190 | b21 | 0.0361085 | 0.037096 | 0.000688 | 0.00012752 | 0.00013072
3 x BLACHA | BL8*126 | +7.623 | +7.811 | 1 | 36.3 | 0 | 126 | 8 | 188 | b5 | 0.0337933 | 0.0236882 | 0.000064 | 0.000118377 | 0.000118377
8 x BLACHA | BL8*86 | +12.354 | +12.529 | 1 | 36.1 | 0 | 86 | 8 | 190 | b21 | 0.0361085 | 0.037096 | 0.000688 | 0.00012752 | 0.00013072
3 x BLACHA | BL8*126 | +12.421 | +12.609 | 1 | 36.3 | 0 | 126 | 8 | 188 | b5 | 0.0337932 | 0.0236881 | 0.000064 | 0.000118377 | 0.000118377
3 x BLACHA | BL8*126 | +7.623 | +7.811 | 1 | 36.3 | 0 | 126 | 8 | 188 | b5 | 0.0337929 | 0.023688 | 0.000064 | 0.000118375 | 0.000118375
3 x BLACHA | BL8*126 | +12.421 | +12.609 | 1 | 36.3 | 0 | 126 | 8 | 188 | b5 | 0.0337927 | 0.0236878 | 0.000064 | 0.000118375 | 0.000118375
6 x BLACHA | BL8*69 | +7.697 | +7.846 | 0.6 | 37.2 | 0 | 69 | 8 | 150 | b15 | 0.024204 | 0.024204 | 0.000552 | 0.0000828 | 0.0000828
6 x BLACHA | BL8*127 | +7.645 | +7.811 | 0.8 | 36.5 | 0 | 126.5 | 8 | 165.9 | xx7 | 0.030562 | 0.0209889 | 0.000064 | 0.000106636 | 0.000106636
3 x BLACHA | BL8*69 | +9.964 | +10.113 | 0.6 | 37.2 | 0 | 69 | 8 | 150 | b15 | 0.024204 | 0.024204 | 0.000552 | 0.0000828 | 0.0000828
3 x BLACHA | BL8*97 | +9.998 | +10.134 | 0.6 | 37.2 | 0 | 96.8 | 8 | 113.9 | b19 | 0.0217249 | 0.011035 | 0.000064 | 0.0000744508 | 0.0000744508
6 x BLACHA | BL8*69 | +12.386 | +12.535 | 0.6 | 37.2 | 0 | 69 | 8 | 150 | b15 | 0.024204 | 0.024204 | 0.000552 | 0.0000828 | 0.0000828
6 x BLACHA | BL8*127 | +12.421 | +12.587 | 0.8 | 36.5 | 0 | 126.5 | 8 | 165.9 | xx7 | 0.030562 | 0.0209889 | 0.000064 | 0.000106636 | 0.000106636
3 x BLACHA | BL8*69 | +10.119 | +10.268 | 0.6 | 37.2 | 0 | 69 | 8 | 150 | b15 | 0.024204 | 0.024204 | 0.000552 | 0.0000828 | 0.0000828
3 x BLACHA | BL8*97 | +10.098 | +10.234 | 0.6 | 37.2 | 0 | 96.8 | 8 | 113.9 | b19 | 0.0217249 | 0.011035 | 0.000064 | 0.0000744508 | 0.0000744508
BLACHA | BL8*126 | +7.623 | +7.811 | 0.8 | 36.3 | 0 | 126 | 8 | 188 | b5 | 0.0337933 | 0.0236882 | 0.000064 | 0.000118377 | 0.000118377
6 x BLACHA | BL8*69 | +7.709 | +7.862 | 0.6 | 37.2 | 0 | 69 | 8 | 150 | b20 | 0.024204 | 0.024204 | 0.000552 | 0.0000828 | 0.0000828
6 x BLACHA | BL8*126 | +7.650 | +7.825 | 0.8 | 36.5 | 0 | 126.3 | 8 | 174.7 | xx4 | 0.0314676 | 0.0220713 | 0.000064 | 0.000109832 | 0.000109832
6 x BLACHA | BL8*69 | +12.370 | +12.523 | 0.6 | 37.2 | 0 | 69 | 8 | 150 | b20 | 0.024204 | 0.024204 | 0.000552 | 0.0000828 | 0.0000828
6 x BLACHA | BL8*126 | +12.407 | +12.582 | 0.8 | 36.5 | 0 | 126.3 | 8 | 174.7 | xx4 | 0.0314676 | 0.0220713 | 0.000064 | 0.000109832 | 0.000109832
4 x BLACHA | BL8*69 | +9.960 | +10.113 | 0.6 | 37.2 | 0 | 69 | 8 | 150 | b15 | 0.024204 | 0.024204 | 0.000552 | 0.0000828 | 0.0000828
4 x BLACHA | BL8*87 | +9.997 | +10.128 | 0.5 | 37.4 | 0 | 86.9 | 8 | 105.9 | b16 | 0.0199917 | 0.00919897 | 0.000064 | 0.0000680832 | 0.0000680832
4 x BLACHA | BL8*69 | +10.119 | +10.272 | 0.6 | 37.2 | 0 | 69 | 8 | 150 | b15 | 0.024204 | 0.024204 | 0.000552 | 0.0000828 | 0.0000828
4 x BLACHA | BL8*87 | +10.104 | +10.235 | 0.5 | 37.4 | 0 | 86.9 | 8 | 105.9 | b16 | 0.0199917 | 0.00919897 | 0.000064 | 0.0000680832 | 0.0000680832
2 x BLACHA | BL8*69 | +7.709 | +7.862 | 0.6 | 37.2 | 0 | 69 | 8 | 150 | b15 | 0.024204 | 0.024204 | 0.000552 | 0.0000828 | 0.0000828
2 x BLACHA | BL8*126 | +7.650 | +7.825 | 0.8 | 36.5 | 0 | 126.3 | 8 | 174.7 | xx3 | 0.0314676 | 0.0220713 | 0.000064 | 0.000109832 | 0.000109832
2 x BLACHA | BL8*69 | +12.370 | +12.523 | 0.6 | 37.2 | 0 | 69 | 8 | 150 | b15 | 0.024204 | 0.024204 | 0.000552 | 0.0000828 | 0.0000828
2 x BLACHA | BL8*126 | +12.407 | +12.582 | 0.8 | 36.5 | 0 | 126.3 | 8 | 174.7 | xx3 | 0.0314676 | 0.0220713 | 0.000064 | 0.000109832 | 0.000109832
BLACHA | BL8*126 | +12.421 | +12.609 | 0.8 | 36.3 | 0 | 126 | 8 | 188 | b5 | 0.0337932 | 0.0236881 | 0.000064 | 0.000118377 | 0.000118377
BLACHA | BL8*126 | +7.623 | +7.811 | 0.8 | 36.3 | 0 | 126 | 8 | 188 | b5 | 0.0337929 | 0.023688 | 0.000064 | 0.000118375 | 0.000118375
BLACHA | BL8*126 | +12.421 | +12.609 | 0.8 | 36.3 | 0 | 126 | 8 | 188 | b5 | 0.0337927 | 0.0236878 | 0.000064 | 0.000118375 | 0.000118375
72 x BLACHA | BL6*60 | +12.827 | +12.833 | 0.3 | 53.3 | 0 | 60 | 6 | 140 | b2 | 0.0148 | 0.0084 | 0.000036 | 0.0000354 | 0.0000354
72 x BLACHA | BL6*117 | +12.821 | +12.827 | 0.5 | 47.7 | 0 | 116.5 | 6 | 165.9 | b1 | 0.0254724 | 0.0193473 | 0.000036 | 0.0000679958 | 0.0000679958

# IfcDiscreteAccessory: COLUMN (24)
In: Undefined
Material: STEEL/S235
Tekla Common - Phase: 2; Class: 4
Tekla Quantity - Volume: 0 m3
Pset_PlateCommon - LoadBearing: no
Name | Description | Bottom elevation | Top elevation | Weight (kg) | Gross footprint area (m2) | Area per tons (m2) | Net surface area (m2) | Height (mm) = Width (mm) | Length (mm) | Reference | NetArea (m2) | GrossArea (m2) | CrossSectionArea (m2) | NetVolume (m3) | GrossVolume (m3)
2 x COLUMN | HEB140 | +12.000 | +12.140 | 180.3 | 0.7 | 23.8 | 4.4 | 140 | 5340 | k108 | 4.2987 | 4.2987 | 0.0043 | 0.0222393 | 0.022962
2 x COLUMN | HEB140 | +8.700 | +8.840 | 180.3 | 0.7 | 23.8 | 4.4 | 140 | 5340 | k108 | 4.2987 | 4.2987 | 0.0043 | 0.0222393 | 0.022962
2 x COLUMN | HEB140 | +5.400 | +5.540 | 180.3 | 0.7 | 23.8 | 4.4 | 140 | 5340 | k108 | 4.2987 | 4.2987 | 0.0043 | 0.0222393 | 0.022962
2 x COLUMN | HEB140 | +2.640 | +2.780 | 153.5 | 0.7 | 23.8 | 3.7 | 140 | 4548.8 | k107 | 3.66179 | 3.66179 | 0.0043 | 0.0188447 | 0.0195599
2 x COLUMN | SHS60*4 | +10.700 | +12.040 | 14.5 | 0 | 34.2 | 0.4 | 60 | 2133.5 | k104 | 0.497623 | 0.509904 | 0.00085095 | 0.00185244 | 0.00189852
2 x COLUMN | SHS60*4 | +7.400 | +8.740 | 14.5 | 0 | 34.2 | 0.4 | 60 | 2133.5 | k104 | 0.497623 | 0.509904 | 0.00085095 | 0.00185244 | 0.00189852
2 x COLUMN | SHS60*4 | +4.100 | +5.440 | 14.5 | 0 | 34.2 | 0.4 | 60 | 2133.5 | k104 | 0.497623 | 0.509904 | 0.00085095 | 0.00185244 | 0.00189852
2 x COLUMN | SHS60*4 | +8.811 | +10.500 | 15.9 | 0 | 34.2 | 0.4 | 60 | 2324.3 | k103 | 0.544774 | 0.544774 | 0.00085095 | 0.00202875 | 0.00202875
2 x COLUMN | SHS60*4 | +5.500 | +7.200 | 16.2 | 0 | 34.2 | 0.6 | 60 | 2351.8 | k102 | 0.553047 | 0.554682 | 0.00085095 | 0.00205975 | 0.00206574
2 x COLUMN | SHS60*4 | +1.960 | +3.900 | 17.3 | 0 | 34.2 | 0.6 | 60 | 2518.9 | k101 | 0.591258 | 0.591258 | 0.00085095 | 0.00220222 | 0.00220222
2 x COLUMN | HEB160 | +1.020 | +5.282 | 191.7 | 0 | 21.5 | 4.2 | 160 | 4497.1 | k97 | 4.12831 | 4.12831 | 0.00543 | 0.0233308 | 0.0244191
2 x COLUMN | HEB160 | +5.258 | +12.160 | 294.2 | 0 | 21.5 | 6.5 | 160 | 6902.4 | k98 | 6.3364 | 6.3364 | 0.00543 | 0.0360485 | 0.03748

# IfcDiscreteAccessory: KRATA
In: Undefined
Description: BL1400*30; Material: STEEL/S235
Tekla Common - Bottom elevation: +2.850; Top elevation: +2.930; Phase: 2; Class: 2
Tekla Quantity - Weight: 889.9 kg; Volume: 0.1 m3; Gross footprint area: 0 m2; Area per tons: 8.7 m2; Net surface area: 7.8 m2; Height: 1400 mm; Width: 30 mm; Length: 2699 mm
Pset_PlateCommon - LoadBearing: no; Reference: A3
BaseQuantities - NetArea: 7.80314 m2; GrossArea: 7.80314 m2; CrossSectionArea: 0.042 m2; NetVolume: 0.113358 m3; GrossVolume: 0.113358 m3

# IfcDiscreteAccessory: STOPNIE (73)
In: Undefined
Description: PL30*300; Material: STEEL/S235JR
Tekla Common - Phase: 2; Class: 2
Tekla Quantity - Weight: 98.9 kg; Volume: 0 m3; Gross footprint area: 0.4 m2; Area per tons: 9.5 m2; Net surface area: 0.8 m2; Height: 300 mm; Width: 30 mm; Length: 1400 mm
Pset_PlateCommon - LoadBearing: yes; Reference: bs1
BaseQuantities - NetArea: 0.942 m2; GrossArea: 0.942 m2; CrossSectionArea: 0.009 m2; NetVolume: 0.0126 m3; GrossVolume: 0.0126 m3
Name | Bottom elevation | Top elevation
STOPNIE | +13.850 | +13.880
STOPNIE | +13.700 | +13.730
STOPNIE | +13.550 | +13.580
STOPNIE | +13.400 | +13.430
STOPNIE | +13.250 | +13.280
STOPNIE | +13.100 | +13.130
STOPNIE | +12.950 | +12.980
STOPNIE | +12.800 | +12.830
STOPNIE | +12.650 | +12.680
STOPNIE | +12.500 | +12.530
STOPNIE | +12.350 | +12.380
STOPNIE | +12.200 | +12.230
STOPNIE | +12.050 | +12.080
STOPNIE | +11.900 | +11.930
STOPNIE | +11.750 | +11.780
STOPNIE | +11.600 | +11.630
STOPNIE | +11.450 | +11.480
STOPNIE | +11.300 | +11.330
STOPNIE | +11.150 | +11.180
STOPNIE | +11.000 | +11.030
STOPNIE | +10.850 | +10.880
STOPNIE | +10.700 | +10.730
STOPNIE | +10.550 | +10.580
STOPNIE | +10.400 | +10.430
STOPNIE | +10.250 | +10.280
STOPNIE | +10.100 | +10.130
STOPNIE | +9.950 | +9.980
STOPNIE | +9.800 | +9.830
STOPNIE | +9.650 | +9.680
STOPNIE | +9.500 | +9.530
STOPNIE | +9.350 | +9.380
STOPNIE | +9.200 | +9.230
STOPNIE | +9.050 | +9.080
STOPNIE | +8.900 | +8.930
STOPNIE | +8.750 | +8.780
STOPNIE | +8.600 | +8.630
STOPNIE | +8.450 | +8.480
STOPNIE | +8.300 | +8.330
STOPNIE | +8.150 | +8.180
STOPNIE | +8.000 | +8.030
STOPNIE | +7.850 | +7.880
STOPNIE | +7.700 | +7.730
STOPNIE | +7.550 | +7.580
STOPNIE | +7.400 | +7.430
STOPNIE | +5.600 | +5.630
STOPNIE | +7.250 | +7.280
STOPNIE | +7.100 | +7.130
STOPNIE | +6.950 | +6.980
STOPNIE | +6.800 | +6.830
STOPNIE | +6.650 | +6.680
STOPNIE | +6.500 | +6.530
STOPNIE | +6.350 | +6.380
STOPNIE | +6.200 | +6.230
STOPNIE | +6.050 | +6.080
STOPNIE | +5.900 | +5.930
STOPNIE | +5.750 | +5.780
STOPNIE | +5.450 | +5.480
STOPNIE | +5.300 | +5.330
STOPNIE | +5.150 | +5.180
STOPNIE | +5.000 | +5.030
STOPNIE | +4.850 | +4.880
STOPNIE | +4.700 | +4.730
STOPNIE | +4.550 | +4.580
STOPNIE | +4.400 | +4.430
STOPNIE | +4.250 | +4.280
STOPNIE | +4.100 | +4.130
STOPNIE | +3.950 | +3.980
STOPNIE | +3.800 | +3.830
STOPNIE | +3.650 | +3.680
STOPNIE | +3.500 | +3.530
STOPNIE | +3.350 | +3.380
STOPNIE | +3.200 | +3.230
STOPNIE | +3.050 | +3.080

# IfcElementAssembly (766)
In: Undefined
Name | PredefinedType | Assembly/Cast unit weight (kg) | Assembly/Cast unit bottom elevation | Assembly/Cast unit top elevation | Assembly/Cast unit position code | Assembly/Cast unit Mark | Width (mm)
Steel Assembly | RIGID_FRAME | 58 | +7.709 | +12.523 | 2-3/A | xx6 | 269.856
Steel Assembly | RIGID_FRAME | 27.9 | +10.119 | +12.523 | 2-3/A | xx4 | 69
Steel Assembly | RIGID_FRAME | 325.5 | +7.491 | +13.880 | 3/A | S20 | 177.8
Steel Assembly | RIGID_FRAME | 325.5 | +7.491 | +13.880 | 2/A | S20 | 177.8
Steel Assembly | RIGID_FRAME | 58 | +7.709 | +12.523 | 2-3/B | xx6 | 269.856
Steel Assembly | RIGID_FRAME | 27.9 | +10.119 | +12.523 | 2-3/B | xx4 | 69
Steel Assembly | RIGID_FRAME | 329.1 | +7.491 | +13.880 | 3/B | S15 | 304.314
Steel Assembly | RIGID_FRAME | 329.1 | +7.491 | +13.880 | 2/B | S16 | 304.314
Steel Assembly | RIGID_FRAME | 27.9 | +7.709 | +10.113 | 2-3/A | xx4 | 69
2 x Steel Assembly | RIGID_FRAME | 18.6 | +7.717 | +10.053 | 2-3/A | St4 | 86
2 x Steel Assembly | RIGID_FRAME | 18.6 | +10.179 | +12.515 | 2-3/A | St4 | 86
Steel Assembly | RIGID_FRAME | 38.1 | +9.939 | +10.293 | 2-3/A | St13 | 354.728
Steel Assembly | RIGID_FRAME | 27.9 | +7.709 | +10.113 | 2-3/B | xx4 | 69
2 x Steel Assembly | RIGID_FRAME | 18.6 | +7.717 | +10.053 | 2-3/B | St4 | 86
2 x Steel Assembly | RIGID_FRAME | 18.6 | +10.179 | +12.515 | 2-3/B | St4 | 86
Steel Assembly | RIGID_FRAME | 38.1 | +9.939 | +10.293 | 2-3/B | St13 | 354.728
Steel Assembly | RIGID_FRAME | 3 | +10.066 | +10.166 | 2/A | St10 | 95.469
Steel Assembly | RIGID_FRAME | 36.8 | +10.066 | +10.166 | 2/B-A | St5 | 100
Steel Assembly | RIGID_FRAME | 3.1 | +10.066 | +10.166 | 2/A | St14 | 185.908
Steel Assembly | RIGID_FRAME | 4 | +10.066 | +10.166 | 2/B | St12 | 185.908
Steel Assembly | RIGID_FRAME | 36.8 | +10.066 | +10.166 | 3/B-A | St5 | 100
Steel Assembly | RIGID_FRAME | 3.1 | +10.066 | +10.166 | 3/A | St14 | 185.908
Steel Assembly | RIGID_FRAME | 4 | +10.066 | +10.166 | 3/B | St12 | 185.908
Steel Assembly | RIGID_FRAME | 3 | +10.066 | +10.166 | 3/A | St10 | 95.469
2 x Steel Assembly | RIGID_FRAME | 19.8 | +7.703 | +10.055 | 1/C-B | St1 | 86
2 x Steel Assembly | RIGID_FRAME | 19.8 | +10.177 | +12.529 | 1/C-B | St1 | 86
Steel Assembly | RIGID_FRAME | 42.8 | +9.940 | +10.292 | 1/C-B | St6 | 352.329
2 x Steel Assembly | RIGID_FRAME | 19.8 | +7.703 | +10.055 | 2/C-B | St1 | 86
2 x Steel Assembly | RIGID_FRAME | 19.8 | +10.177 | +12.529 | 2/C-B | St1 | 86
Steel Assembly | RIGID_FRAME | 42.8 | +9.940 | +10.292 | 2/C-B | St6 | 352.329
Steel Assembly | RIGID_FRAME | 325.5 | +7.491 | +13.880 | 1/C | S17 | 304.314
Steel Assembly | RIGID_FRAME | 325.5 | +7.491 | +13.880 | 1/B | S17 | 304.314
Steel Assembly | RIGID_FRAME | 329.1 | +7.491 | +13.880 | 2/C | S15 | 304.314
2 x Steel Assembly | RIGID_FRAME | 19.8 | +7.703 | +10.055 | 3/C-B | St1 | 86
2 x Steel Assembly | RIGID_FRAME | 19.8 | +10.177 | +12.529 | 3/C-B | St1 | 86
Steel Assembly | RIGID_FRAME | 42.8 | +9.940 | +10.292 | 3/C-B | St6 | 352.329
Steel Assembly | RIGID_FRAME | 329.1 | +7.491 | +13.880 | 3/C | S16 | 304.314
Steel Assembly | RIGID_FRAME | 3.6 | +10.066 | +10.166 | 1/C | St9 | 185.908
Steel Assembly | RIGID_FRAME | 3.1 | +10.066 | +10.166 | 1/B | St14 | 185.908
Steel Assembly | RIGID_FRAME | 3 | +10.066 | +10.166 | 1/B | St10 | 95.469
Steel Assembly | RIGID_FRAME | 32.5 | +10.066 | +10.166 | 1-2/B | St11 | 100
Steel Assembly | RIGID_FRAME | 3.1 | +10.066 | +10.166 | 2/B | St14 | 185.908
Steel Assembly | RIGID_FRAME | 3.1 | +10.066 | +10.166 | 3/B | St14 | 185.908
Steel Assembly | RIGID_FRAME | 58 | +7.709 | +12.523 | 2-3/C | xx6 | 269.856
Steel Assembly | RIGID_FRAME | 27.9 | +7.709 | +10.113 | 2-3/C | xx4 | 69
Steel Assembly | RIGID_FRAME | 27.9 | +10.119 | +12.523 | 2-3/C | xx4 | 69
2 x Steel Assembly | RIGID_FRAME | 18.6 | +7.717 | +10.053 | 2-3/C | St4 | 86
2 x Steel Assembly | RIGID_FRAME | 18.6 | +10.179 | +12.515 | 2-3/C | St4 | 86
Steel Assembly | RIGID_FRAME | 38.1 | +9.939 | +10.293 | 2-3/C | St13 | 354.728
Steel Assembly | RIGID_FRAME | 36.8 | +10.066 | +10.166 | 1/D-C | St5 | 100
Steel Assembly | RIGID_FRAME | 3.1 | +10.066 | +10.166 | 1/C | St14 | 185.908
Steel Assembly | RIGID_FRAME | 3.6 | +10.066 | +10.166 | 1/D | St9 | 185.908
Steel Assembly | RIGID_FRAME | 42.8 | +9.940 | +10.292 | 4/C-B | St6 | 352.329
Steel Assembly | RIGID_FRAME | 3.1 | +10.066 | +10.166 | 4/B | St14 | 185.908
Steel Assembly | RIGID_FRAME | 3 | +10.066 | +10.166 | 4/B | St10 | 95.469
Steel Assembly | RIGID_FRAME | 32.5 | +10.066 | +10.166 | 3-4/B | St11 | 100
2 x Steel Assembly | RIGID_FRAME | 18.6 | +7.717 | +10.053 | 2-3/E | St4 | 86
2 x Steel Assembly | RIGID_FRAME | 19.8 | +7.703 | +10.055 | 4/C-B | St1 | 86
2 x Steel Assembly | RIGID_FRAME | 19.8 | +10.177 | +12.529 | 4/C-B | St1 | 86
Steel Assembly | RIGID_FRAME | 4 | +10.066 | +10.166 | 2/C | St12 | 185.908
Steel Assembly | RIGID_FRAME | 36.8 | +10.066 | +10.166 | 2/D-C | St5 | 100
Steel Assembly | RIGID_FRAME | 3.1 | +10.066 | +10.166 | 2/C | St14 | 185.908
Steel Assembly | RIGID_FRAME | 32.5 | +10.066 | +10.166 | 1-2/C | St11 | 100
Steel Assembly | RIGID_FRAME | 4 | +10.066 | +10.166 | 3/C | St12 | 185.908
Steel Assembly | RIGID_FRAME | 32.5 | +10.066 | +10.166 | 3-4/C | St11 | 100
Steel Assembly | RIGID_FRAME | 36.8 | +10.066 | +10.166 | 3/D-C | St5 | 100
Steel Assembly | RIGID_FRAME | 3.1 | +10.066 | +10.166 | 3/C | St14 | 185.908
Steel Assembly | RIGID_FRAME | 36.8 | +10.066 | +10.166 | 4/D-C | St5 | 100
Steel Assembly | RIGID_FRAME | 3.1 | +10.066 | +10.166 | 4/C | St14 | 185.908
Steel Assembly | RIGID_FRAME | 3.6 | +10.066 | +10.166 | 4/C | St9 | 185.908
Steel Assembly | RIGID_FRAME | 3.6 | +10.066 | +10.166 | 4/D | St9 | 185.908
Steel Assembly | RIGID_FRAME | 2.5 | +10.066 | +10.166 | 4/D | St7 | 95.469
Steel Assembly | RIGID_FRAME | 4 | +10.066 | +10.166 | 3/D | St12 | 185.908
Steel Assembly | RIGID_FRAME | 32.5 | +10.066 | +10.166 | 3-4/D | St11 | 100
Steel Assembly | RIGID_FRAME | 2.5 | +10.066 | +10.166 | 1/D | St7 | 95.469
Steel Assembly | RIGID_FRAME | 4 | +10.066 | +10.166 | 2/D | St12 | 185.908
Steel Assembly | RIGID_FRAME | 32.5 | +10.066 | +10.166 | 1-2/D | St11 | 100
Steel Assembly | RIGID_FRAME | 36.8 | +10.066 | +10.166 | 2/E-D | St5 | 100
Steel Assembly | RIGID_FRAME | 3.1 | +10.066 | +10.166 | 2/D | St14 | 185.908
Steel Assembly | RIGID_FRAME | 36.8 | +10.066 | +10.166 | 3/E-D | St5 | 100
Steel Assembly | RIGID_FRAME | 3.1 | +10.066 | +10.166 | 3/D | St14 | 185.908
2 x Steel Assembly | RIGID_FRAME | 18.6 | +7.717 | +10.053 | 2-3/D | St4 | 86
Steel Assembly | RIGID_FRAME | 38.1 | +9.939 | +10.293 | 2-3/D | St3 | 354.728
2 x Steel Assembly | RIGID_FRAME | 18.6 | +10.179 | +12.515 | 2-3/D | St4 | 86
Steel Assembly | RIGID_FRAME | 325.5 | +7.491 | +13.880 | 2/D | S19 | 177.8
Steel Assembly | RIGID_FRAME | 325.5 | +7.491 | +13.880 | 3/D | S21 | 188.8
Steel Assembly | RIGID_FRAME | 38.1 | +9.939 | +10.293 | 2-3/E | St3 | 354.728
2 x Steel Assembly | RIGID_FRAME | 18.6 | +10.179 | +12.515 | 2-3/E | St4 | 86
Steel Assembly | RIGID_FRAME | 323.8 | +7.491 | +13.880 | 2/E | S18 | 177.8
Steel Assembly | RIGID_FRAME | 3.6 | +10.066 | +10.166 | 2/E | St9 | 185.908
Steel Assembly | RIGID_FRAME | 2.5 | +10.066 | +10.166 | 2/E | St7 | 95.469
Steel Assembly | RIGID_FRAME | 3.6 | +10.066 | +10.166 | 3/E | St9 | 185.908
Steel Assembly | RIGID_FRAME | 2.5 | +10.066 | +10.166 | 3/E | St7 | 95.469
Steel Assembly | RIGID_FRAME | 323.8 | +7.491 | +13.880 | 3/E | S14 | 188.8
Steel Assembly | RIGID_FRAME | 29.8 | +7.697 | +10.113 | 1/C-B | xx1 | 69
Steel Assembly | RIGID_FRAME | 62 | +7.697 | +12.535 | 1/C-B | xx2 | 282.746
Steel Assembly | RIGID_FRAME | 29.8 | +10.119 | +12.535 | 1/C-B | xx1 | 69
Steel Assembly | RIGID_FRAME | 29.8 | +7.697 | +10.113 | 2/C-B | xx1 | 69
Steel Assembly | RIGID_FRAME | 62 | +7.697 | +12.535 | 2/C-B | xx2 | 282.746
Steel Assembly | RIGID_FRAME | 29.8 | +10.119 | +12.535 | 2/C-B | xx1 | 69
Steel Assembly | RIGID_FRAME | 29.8 | +7.697 | +10.113 | 3/C-B | xx1 | 69
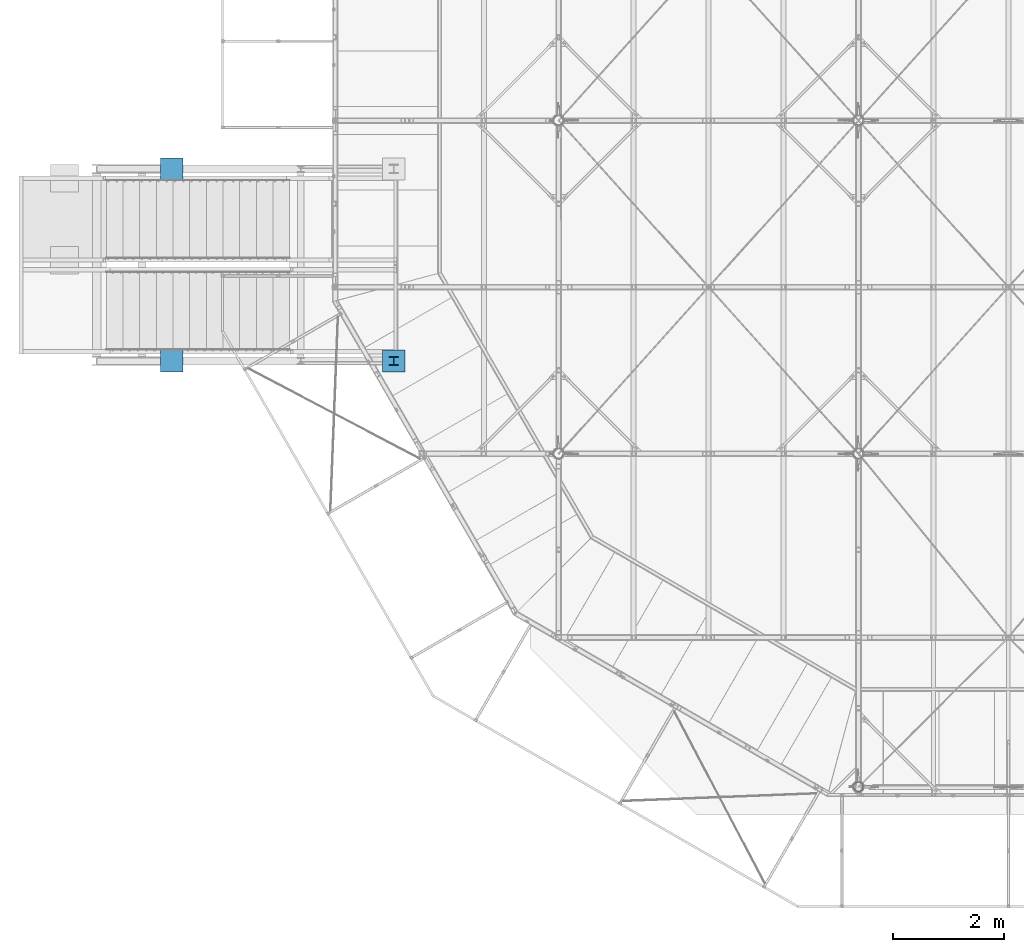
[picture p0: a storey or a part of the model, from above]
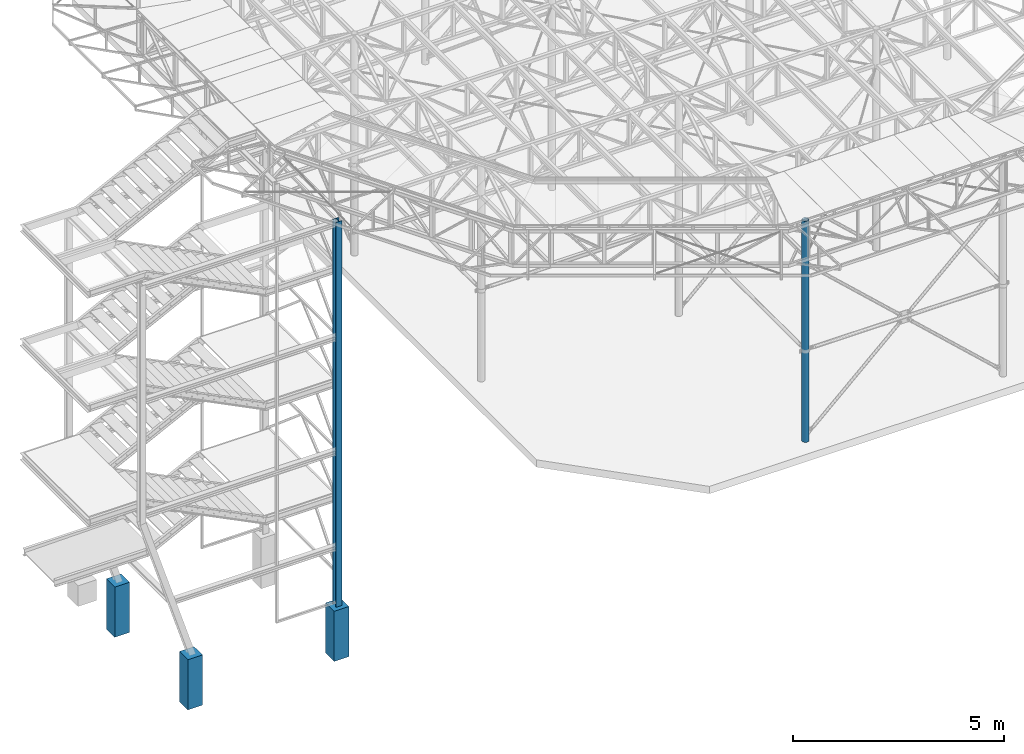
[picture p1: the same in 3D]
Properties of the parts of a building model (IFC2X3), part 2 of 2

# IfcElementAssembly (766)
Name | PredefinedType | Assembly/Cast unit weight (kg) | Assembly/Cast unit bottom elevation | Assembly/Cast unit top elevation | Assembly/Cast unit position code | Assembly/Cast unit Mark | Width (mm)
Steel Assembly | RIGID_FRAME | 62 | +7.697 | +12.535 | 3/C-B | xx2 | 282.746
Steel Assembly | RIGID_FRAME | 29.8 | +10.119 | +12.535 | 3/C-B | xx1 | 69
Steel Assembly | RIGID_FRAME | 323.8 | +7.491 | +13.880 | 4/C | S13 | 303.801
Steel Assembly | RIGID_FRAME | 27.9 | +7.709 | +10.113 | 2-3/D | xx3 | 69
Steel Assembly | RIGID_FRAME | 58 | +7.709 | +12.523 | 2-3/D | xx5 | 269.856
Steel Assembly | RIGID_FRAME | 27.9 | +10.119 | +12.523 | 2-3/D | xx3 | 69
Steel Assembly | RIGID_FRAME | 36.8 | +14.030 | +14.032 | 4-4'/C-B | A23 | 2
2 x Steel Assembly | RIGID_FRAME | 32.8 | +14.030 | +14.032 | 4-4'/C-B | A18 | 2
Steel Assembly | RIGID_FRAME | 32.8 | +14.030 | +14.032 | 4-4'/C-A' | A18 | 2
Steel Assembly | RIGID_FRAME | 32.8 | +14.030 | +14.032 | 4-4'/B-A' | A18 | 2
Steel Assembly | RIGID_FRAME | 24.4 | +14.030 | +14.032 | 3-4'/B-A' | A19 | 2
Steel Assembly | RIGID_FRAME | 24.4 | +14.030 | +14.032 | 3-4/A'-A | A19 | 2
Steel Assembly | RIGID_FRAME | 24.4 | +14.030 | +14.032 | 3-4'/B-A' | A20 | 2
3 x Steel Assembly | RIGID_FRAME | 32.8 | +14.030 | +14.032 | 3-4/B-A | A18 | 2
Steel Assembly | RIGID_FRAME | 32.8 | +14.030 | +14.032 | 3-4/A'-A | A18 | 2
Steel Assembly | RIGID_FRAME | 16.4 | +14.030 | +14.032 | 3-4/A'-A | A12 | 2
Steel Assembly | RIGID_FRAME | 24.4 | +14.030 | +14.032 | 3-4/A'-A | A20 | 2
Steel Assembly | RIGID_FRAME | 16.4 | +14.030 | +14.032 | 2-3/A'-A | A12 | 2
4 x Steel Assembly | RIGID_FRAME | 32.8 | +14.030 | +14.032 | 2-3/A'-A | A18 | 2
Steel Assembly | RIGID_FRAME | 24.4 | +14.030 | +14.032 | 1-2/A'-A | A20 | 2
3 x Steel Assembly | RIGID_FRAME | 32.8 | +14.030 | +14.032 | 1-2/B-A | A18 | 2
Steel Assembly | RIGID_FRAME | 32.8 | +14.030 | +14.032 | 1-2/A'-A | A18 | 2
Steel Assembly | RIGID_FRAME | 16.4 | +14.030 | +14.032 | 1-2/A'-A | A12 | 2
Steel Assembly | RIGID_FRAME | 24.4 | +14.030 | +14.032 | 1-2/A'-A | A19 | 2
Steel Assembly | RIGID_FRAME | 24.4 | +14.030 | +14.032 | 1'-1/C-B | A19 | 2
4 x Steel Assembly | RIGID_FRAME | 32.8 | +14.030 | +14.032 | 1'-1/C-B | A18 | 2
Steel Assembly | RIGID_FRAME | 32.8 | +14.030 | +14.032 | 1'-1/C-A' | A18 | 2
Steel Assembly | RIGID_FRAME | 32.8 | +14.030 | +14.032 | 1'-1/B-A' | A18 | 2
Steel Assembly | RIGID_FRAME | 16.4 | +14.030 | +14.032 | 1'-1/B-A' | A12 | 2
Steel Assembly | RIGID_FRAME | 24.4 | +14.030 | +14.032 | 1'-2/B-A' | A20 | 2
Steel Assembly | RIGID_FRAME | 24.4 | +14.030 | +14.032 | 1'-2/B-A' | A19 | 2
Steel Assembly | RIGID_FRAME | 24.4 | +14.030 | +14.032 | 1'-1/C-B | A20 | 2
4 x Steel Assembly | RIGID_FRAME | 32.8 | +14.030 | +14.032 | 1'-1/D-C | A18 | 2
Steel Assembly | RIGID_FRAME | 16.4 | +14.030 | +14.032 | 1'-1/C | A12 | 2
Steel Assembly | RIGID_FRAME | 24.4 | +14.030 | +14.032 | 1'-1/D-C | A19 | 2
Steel Assembly | RIGID_FRAME | 24.4 | +14.030 | +14.032 | 1'-1/D-C | A20 | 2
Steel Assembly | RIGID_FRAME | 32.8 | +14.030 | +14.032 | 1'-1/D'-C | A18 | 2
Steel Assembly | RIGID_FRAME | 32.8 | +14.030 | +14.032 | 1'-1/D'-D | A18 | 2
Steel Assembly | RIGID_FRAME | 16.4 | +14.030 | +14.032 | 1'-1/D'-D | A12 | 2
Steel Assembly | RIGID_FRAME | 24.4 | +14.030 | +14.032 | 1'-2/D'-D | A19 | 2
Steel Assembly | RIGID_FRAME | 24.4 | +14.030 | +14.032 | 1'-2/D'-D | A20 | 2
3 x Steel Assembly | RIGID_FRAME | 32.8 | +14.030 | +14.032 | 1-2/E-D | A18 | 2
Steel Assembly | RIGID_FRAME | 32.8 | +14.030 | +14.032 | 1-2/E-D' | A18 | 2
Steel Assembly | RIGID_FRAME | 16.4 | +14.030 | +14.032 | 1-2/E-D' | A12 | 2
Steel Assembly | RIGID_FRAME | 24.4 | +14.030 | +14.032 | 1-2/E-D' | A19 | 2
Steel Assembly | RIGID_FRAME | 24.4 | +14.030 | +14.032 | 1-2/E-D' | A20 | 2
Steel Assembly | RIGID_FRAME | 16.4 | +14.030 | +14.032 | 2-3/E-D' | A12 | 2
4 x Steel Assembly | RIGID_FRAME | 32.8 | +14.030 | +14.032 | 2-3/E-D' | A18 | 2
Steel Assembly | RIGID_FRAME | 24.4 | +14.030 | +14.032 | 3-4/E-D' | A20 | 2
Steel Assembly | RIGID_FRAME | 24.4 | +14.030 | +14.032 | 3-4/E-D' | A19 | 2
Steel Assembly | RIGID_FRAME | 24.4 | +14.030 | +14.032 | 3-4'/D'-D | A19 | 2
3 x Steel Assembly | RIGID_FRAME | 32.8 | +14.030 | +14.032 | 3-4/E-D | A18 | 2
Steel Assembly | RIGID_FRAME | 32.8 | +14.030 | +14.032 | 3-4/E-D' | A18 | 2
Steel Assembly | RIGID_FRAME | 16.4 | +14.030 | +14.032 | 3-4/E-D' | A12 | 2
Steel Assembly | RIGID_FRAME | 36.8 | +14.030 | +14.032 | 4-4'/D-C | A22 | 2
2 x Steel Assembly | RIGID_FRAME | 32.8 | +14.030 | +14.032 | 4-4'/D-C | A18 | 2
Steel Assembly | RIGID_FRAME | 32.8 | +14.030 | +14.032 | 4-4'/D'-C | A18 | 2
Steel Assembly | RIGID_FRAME | 32.8 | +14.030 | +14.032 | 4-4'/D'-D | A18 | 2
Steel Assembly | RIGID_FRAME | 24.4 | +14.030 | +14.032 | 3-4'/D'-D | A20 | 2
Steel Assembly | RIGID_FRAME | 1676.4 | +1.020 | +12.160 | 1'-1/D-C | S6 | 5510
2 x Steel Assembly | RIGID_FRAME | 18.4 | +2.780 | +5.400 | <1'/D-C | B1 | 60
2 x Steel Assembly | RIGID_FRAME | 22.2 | +8.840 | +12.000 | <1'/D-C | B2 | 60
2 x Steel Assembly | RIGID_FRAME | 22.2 | +5.540 | +8.700 | <1'/D-C | B2 | 60
Steel Assembly | RIGID_FRAME | 1676.4 | +1.020 | +12.160 | 1'-1/D-C | S5 | 5510
Steel Assembly | RIGID_FRAME | 177.8 | +12.140 | +13.800 | <1'/D-C | B3 | 120
Steel Assembly | RIGID_FRAME | 247.3 | +14.000 | +14.030 | <1'/D-C | SCH2 | 30
Steel Assembly | RIGID_FRAME | 1077.4 | +12.350 | +12.380 | <1'/D-C | A2 | 30
Steel Assembly | RIGID_FRAME | 99.5 | +13.810 | +13.880 | <1'/D-C | SCH1 | 70
Steel Assembly | RIGID_FRAME | 99.5 | +13.660 | +13.730 | <1'/D-C | SCH1 | 70
Steel Assembly | RIGID_FRAME | 99.5 | +13.510 | +13.580 | <1'/D-C | SCH1 | 70
Steel Assembly | RIGID_FRAME | 99.5 | +13.360 | +13.430 | <1'/D-C | SCH1 | 70
Steel Assembly | RIGID_FRAME | 99.5 | +13.210 | +13.280 | <1'/D-C | SCH1 | 70
Steel Assembly | RIGID_FRAME | 99.5 | +13.060 | +13.130 | <1'/D-C | SCH1 | 70
Steel Assembly | RIGID_FRAME | 99.5 | +12.910 | +12.980 | <1'/D-C | SCH1 | 70
Steel Assembly | RIGID_FRAME | 99.5 | +12.760 | +12.830 | <1'/D-C | SCH1 | 70
Steel Assembly | RIGID_FRAME | 99.5 | +12.610 | +12.680 | <1'/D-C | SCH1 | 70
Steel Assembly | RIGID_FRAME | 99.5 | +12.460 | +12.530 | <1'/D-C | SCH1 | 70
Steel Assembly | RIGID_FRAME | 99.5 | +12.310 | +12.380 | <1'/D-C | SCH1 | 70
Steel Assembly | RIGID_FRAME | 151.5 | +12.150 | +14.000 | <1'/D-C | A7 | 75
Steel Assembly | RIGID_FRAME | 151.5 | +12.150 | +14.000 | <1'/D-C | A5 | 75
Steel Assembly | RIGID_FRAME | 1077.4 | +9.050 | +9.080 | <1'/D-C | A2 | 30
Steel Assembly | RIGID_FRAME | 1077.4 | +5.750 | +5.780 | <1'/D-C | A2 | 30
Steel Assembly | RIGID_FRAME | 1346.8 | +10.700 | +10.730 | <1'-1/D-C | SCH3 | 30
Steel Assembly | RIGID_FRAME | 1346.8 | +7.400 | +7.430 | <1'-1/D-C | A13 | 30
Steel Assembly | RIGID_FRAME | 80.9 | +12.150 | +12.350 | <1'/D-C | A1 | 75
Steel Assembly | RIGID_FRAME | 99.5 | +12.160 | +12.230 | <1'/D-C | SCH1 | 70
Steel Assembly | RIGID_FRAME | 99.5 | +12.010 | +12.080 | <1'/D-C | SCH1 | 70
Steel Assembly | RIGID_FRAME | 99.5 | +11.860 | +11.930 | <1'/D-C | SCH1 | 70
Steel Assembly | RIGID_FRAME | 99.5 | +11.710 | +11.780 | <1'/D-C | SCH1 | 70
Steel Assembly | RIGID_FRAME | 99.5 | +11.560 | +11.630 | <1'/D-C | SCH1 | 70
Steel Assembly | RIGID_FRAME | 99.5 | +11.410 | +11.480 | <1'/D-C | SCH1 | 70
Steel Assembly | RIGID_FRAME | 99.5 | +11.260 | +11.330 | <1'/D-C | SCH1 | 70
Steel Assembly | RIGID_FRAME | 99.5 | +11.110 | +11.180 | <1'/D-C | SCH1 | 70
Steel Assembly | RIGID_FRAME | 99.5 | +10.960 | +11.030 | <1'/D-C | SCH1 | 70
Steel Assembly | RIGID_FRAME | 99.5 | +10.810 | +10.880 | <1'/D-C | SCH1 | 70
Steel Assembly | RIGID_FRAME | 99.5 | +10.660 | +10.730 | <1'/D-C | SCH1 | 70
Steel Assembly | RIGID_FRAME | 181 | +10.500 | +12.350 | <1'/D-C | A8 | 75
Steel Assembly | RIGID_FRAME | 181 | +10.500 | +12.350 | <1'/D-C | A9 | 75
Steel Assembly | RIGID_FRAME | 99.5 | +10.510 | +10.580 | <1'/D-C | SCH1 | 70
Steel Assembly | RIGID_FRAME | 99.5 | +10.360 | +10.430 | <1'/D-C | SCH1 | 70
Steel Assembly | RIGID_FRAME | 99.5 | +10.210 | +10.280 | <1'/D-C | SCH1 | 70
Steel Assembly | RIGID_FRAME | 99.5 | +10.060 | +10.130 | <1'/D-C | SCH1 | 70
Steel Assembly | RIGID_FRAME | 99.5 | +9.910 | +9.980 | <1'/D-C | SCH1 | 70
Steel Assembly | RIGID_FRAME | 99.5 | +9.760 | +9.830 | <1'/D-C | SCH1 | 70
Steel Assembly | RIGID_FRAME | 99.5 | +9.610 | +9.680 | <1'/D-C | SCH1 | 70
Steel Assembly | RIGID_FRAME | 99.5 | +9.460 | +9.530 | <1'/D-C | SCH1 | 70
Steel Assembly | RIGID_FRAME | 99.5 | +9.310 | +9.380 | <1'/D-C | SCH1 | 70
Steel Assembly | RIGID_FRAME | 99.5 | +9.160 | +9.230 | <1'/D-C | SCH1 | 70
Steel Assembly | RIGID_FRAME | 99.5 | +9.010 | +9.080 | <1'/D-C | SCH1 | 70
Steel Assembly | RIGID_FRAME | 181 | +8.850 | +10.700 | <1'/D-C | A6 | 75
Steel Assembly | RIGID_FRAME | 181 | +8.850 | +10.700 | <1'/D-C | A4 | 75
Steel Assembly | RIGID_FRAME | 80.9 | +8.850 | +9.050 | <1'/D-C | A1 | 75
Steel Assembly | RIGID_FRAME | 99.5 | +8.860 | +8.930 | <1'/D-C | SCH1 | 70
Steel Assembly | RIGID_FRAME | 99.5 | +8.710 | +8.780 | <1'/D-C | SCH1 | 70
Steel Assembly | RIGID_FRAME | 99.5 | +8.560 | +8.630 | <1'/D-C | SCH1 | 70
Steel Assembly | RIGID_FRAME | 99.5 | +8.410 | +8.480 | <1'/D-C | SCH1 | 70
Steel Assembly | RIGID_FRAME | 99.5 | +8.260 | +8.330 | <1'/D-C | SCH1 | 70
Steel Assembly | RIGID_FRAME | 99.5 | +8.110 | +8.180 | <1'/D-C | SCH1 | 70
Steel Assembly | RIGID_FRAME | 99.5 | +7.960 | +8.030 | <1'/D-C | SCH1 | 70
Steel Assembly | RIGID_FRAME | 99.5 | +7.810 | +7.880 | <1'/D-C | SCH1 | 70
Steel Assembly | RIGID_FRAME | 99.5 | +7.660 | +7.730 | <1'/D-C | SCH1 | 70
Steel Assembly | RIGID_FRAME | 99.5 | +7.510 | +7.580 | <1'/D-C | SCH1 | 70
Steel Assembly | RIGID_FRAME | 99.5 | +7.360 | +7.430 | <1'/D-C | SCH1 | 70
Steel Assembly | RIGID_FRAME | 181 | +7.200 | +9.050 | <1'/D-C | A8 | 75
Steel Assembly | RIGID_FRAME | 181 | +7.200 | +9.050 | <1'/D-C | A9 | 75
Steel Assembly | RIGID_FRAME | 99.5 | +5.560 | +5.630 | <1'/D-C | SCH1 | 70
Steel Assembly | RIGID_FRAME | 99.5 | +7.210 | +7.280 | <1'/D-C | SCH1 | 70
Steel Assembly | RIGID_FRAME | 99.5 | +7.060 | +7.130 | <1'/D-C | SCH1 | 70
Steel Assembly | RIGID_FRAME | 99.5 | +6.910 | +6.980 | <1'/D-C | SCH1 | 70
Steel Assembly | RIGID_FRAME | 99.5 | +6.760 | +6.830 | <1'/D-C | SCH1 | 70
Steel Assembly | RIGID_FRAME | 99.5 | +6.610 | +6.680 | <1'/D-C | SCH1 | 70
Steel Assembly | RIGID_FRAME | 99.5 | +6.460 | +6.530 | <1'/D-C | SCH1 | 70
Steel Assembly | RIGID_FRAME | 99.5 | +6.310 | +6.380 | <1'/D-C | SCH1 | 70
Steel Assembly | RIGID_FRAME | 99.5 | +6.160 | +6.230 | <1'/D-C | SCH1 | 70
Steel Assembly | RIGID_FRAME | 99.5 | +6.010 | +6.080 | <1'/D-C | SCH1 | 70
Steel Assembly | RIGID_FRAME | 99.5 | +5.860 | +5.930 | <1'/D-C | SCH1 | 70
Steel Assembly | RIGID_FRAME | 99.5 | +5.710 | +5.780 | <1'/D-C | SCH1 | 70
Steel Assembly | RIGID_FRAME | 181 | +5.550 | +7.400 | <1'/D-C | A6 | 75
Steel Assembly | RIGID_FRAME | 181 | +5.550 | +7.400 | <1'/D-C | A4 | 75
Steel Assembly | RIGID_FRAME | 889.9 | +2.850 | +2.930 | <1'/D-C | A3 | 30
Steel Assembly | RIGID_FRAME | 1346.8 | +4.100 | +4.130 | <1'-1/D-C | A13 | 30
Steel Assembly | RIGID_FRAME | 99.5 | +5.410 | +5.480 | <1'/D-C | SCH1 | 70
Steel Assembly | RIGID_FRAME | 80.9 | +5.550 | +5.750 | <1'/D-C | A1 | 75
Steel Assembly | RIGID_FRAME | 99.5 | +5.260 | +5.330 | <1'/D-C | SCH1 | 70
Steel Assembly | RIGID_FRAME | 99.5 | +5.110 | +5.180 | <1'/D-C | SCH1 | 70
Steel Assembly | RIGID_FRAME | 99.5 | +4.960 | +5.030 | <1'/D-C | SCH1 | 70
Steel Assembly | RIGID_FRAME | 99.5 | +4.810 | +4.880 | <1'/D-C | SCH1 | 70
Steel Assembly | RIGID_FRAME | 99.5 | +4.660 | +4.730 | <1'/D-C | SCH1 | 70
Steel Assembly | RIGID_FRAME | 99.5 | +4.510 | +4.580 | <1'/D-C | SCH1 | 70
Steel Assembly | RIGID_FRAME | 99.5 | +4.360 | +4.430 | <1'/D-C | SCH1 | 70
Steel Assembly | RIGID_FRAME | 99.5 | +4.210 | +4.280 | <1'/D-C | SCH1 | 70
Steel Assembly | RIGID_FRAME | 99.5 | +4.060 | +4.130 | <1'/D-C | SCH1 | 70
Steel Assembly | RIGID_FRAME | 181 | +3.900 | +5.750 | <1'/D-C | A8 | 75
Steel Assembly | RIGID_FRAME | 181 | +3.900 | +5.750 | <1'/D-C | A9 | 75
2 x COLUMN | REINFORCEMENT_UNIT | 360 | +2.180 | +2.780 | <1'/D-C | S1 | 500 | Tekla Assembly - Cast unit type: Wylewany na miejscu; Cast unit rebar weight: 0 kg
2 x COLUMN | REINFORCEMENT_UNIT | 556.8 | -0.430 | +1.020 | <1'/D-C | S4 | 400 | Tekla Assembly - Cast unit type: Wylewany na miejscu; Cast unit rebar weight: 0 kg
Steel Assembly | RIGID_FRAME | 99.5 | +3.910 | +3.980 | <1'/D-C | SCH1 | 70
Steel Assembly | RIGID_FRAME | 99.5 | +3.760 | +3.830 | <1'/D-C | SCH1 | 70
Steel Assembly | RIGID_FRAME | 99.5 | +3.610 | +3.680 | <1'/D-C | SCH1 | 70
Steel Assembly | RIGID_FRAME | 99.5 | +3.460 | +3.530 | <1'/D-C | SCH1 | 70
Steel Assembly | RIGID_FRAME | 99.5 | +3.310 | +3.380 | <1'/D-C | SCH1 | 70
Steel Assembly | RIGID_FRAME | 99.5 | +3.160 | +3.230 | <1'/D-C | SCH1 | 70
Steel Assembly | RIGID_FRAME | 99.5 | +3.010 | +3.080 | <1'/D-C | SCH1 | 70
Steel Assembly | RIGID_FRAME | 177.8 | +2.780 | +4.100 | <1'/D-C | A11 | 75
Steel Assembly | RIGID_FRAME | 177.8 | +2.780 | +4.100 | <1'/D-C | A10 | 75
Steel Assembly | RIGID_FRAME | 140.7 | +11.990 | +12.150 | <1'/D-C | S2 | 160
Steel Assembly | RIGID_FRAME | 140.7 | +8.690 | +8.850 | <1'/D-C | S2 | 160
Steel Assembly | RIGID_FRAME | 140.7 | +5.390 | +5.550 | <1'/D-C | S2 | 160
Steel Assembly | RIGID_FRAME | 111.4 | +2.640 | +2.780 | <1'/D-C | S3 | 140
Steel Assembly | RIGID_FRAME | 52.3 | +10.700 | +12.100 | 1'-1/D-C | S8 | 60
Steel Assembly | RIGID_FRAME | 52.3 | +7.400 | +8.800 | 1'-1/D-C | S8 | 60
Steel Assembly | RIGID_FRAME | 52.3 | +4.100 | +5.500 | 1'-1/D-C | S8 | 60
Steel Assembly | RIGID_FRAME | 113.5 | +8.811 | +10.700 | 1'-1/D-C | S11 | 80
Steel Assembly | RIGID_FRAME | 113.9 | +5.500 | +7.400 | 1'-1/D-C | S10 | 80
Steel Assembly | RIGID_FRAME | 116.2 | +1.960 | +4.100 | 1'-1/D-C | S9 | 80
Steel Assembly | RIGID_FRAME | 23.2 | +1.880 | +1.940 | 1'-1/D-C | S7 | 60
2 x COLUMN | REINFORCEMENT_UNIT | 556.8 | -0.430 | +1.020 | 1'-1/D-C | S4 | 400 | Tekla Assembly - Cast unit type: Wylewany na miejscu; Cast unit rebar weight: 0 kg
Steel Assembly | RIGID_FRAME | 686.2 | +13.990 | +14.030 | 4-4'/C-B | A17 | 40
2 x Steel Assembly | RIGID_FRAME | 612.6 | +13.990 | +14.030 | 4-4'/C-B | A15 | 40
Steel Assembly | RIGID_FRAME | 612.6 | +13.990 | +14.030 | 4-4'/C-A' | A15 | 40
Steel Assembly | RIGID_FRAME | 612.6 | +13.990 | +14.030 | 4-4'/B-A' | A15 | 40
2 x Steel Assembly | RIGID_FRAME | 454.6 | +13.990 | +14.030 | 3-4'/B-A' | A16 | 40
Steel Assembly | RIGID_FRAME | 686.2 | +13.990 | +14.030 | 4-4'/D-C | A17 | 40
2 x Steel Assembly | RIGID_FRAME | 612.6 | +13.990 | +14.030 | 4-4'/D-C | A15 | 40
Steel Assembly | RIGID_FRAME | 612.6 | +13.990 | +14.030 | 4-4'/D'-C | A15 | 40
Steel Assembly | RIGID_FRAME | 612.6 | +13.990 | +14.030 | 4-4'/D'-D | A15 | 40
2 x Steel Assembly | RIGID_FRAME | 454.6 | +13.990 | +14.030 | 3-4/E-D' | A16 | 40
2 x Steel Assembly | RIGID_FRAME | 454.6 | +13.990 | +14.030 | 3-4'/D'-D | A16 | 40
3 x Steel Assembly | RIGID_FRAME | 612.6 | +13.990 | +14.030 | 3-4/E-D | A15 | 40
Steel Assembly | RIGID_FRAME | 612.6 | +13.990 | +14.030 | 3-4/E-D' | A15 | 40
Steel Assembly | RIGID_FRAME | 306.3 | +13.990 | +14.030 | 3-4/E-D' | A14 | 40
2 x Steel Assembly | RIGID_FRAME | 454.6 | +13.990 | +14.030 | 3-4/A'-A | A16 | 40
3 x Steel Assembly | RIGID_FRAME | 612.6 | +13.990 | +14.030 | 3-4/B-A | A15 | 40
Steel Assembly | RIGID_FRAME | 612.6 | +13.990 | +14.030 | 3-4/A'-A | A15 | 40
Steel Assembly | RIGID_FRAME | 306.3 | +13.990 | +14.030 | 3-4/A'-A | A14 | 40
2 x Steel Assembly | RIGID_FRAME | 454.6 | +13.990 | +14.030 | 1'-1/C-B | A16 | 40
4 x Steel Assembly | RIGID_FRAME | 612.6 | +13.990 | +14.030 | 1'-1/C-B | A15 | 40
Steel Assembly | RIGID_FRAME | 612.6 | +13.990 | +14.030 | 1'-1/C-A' | A15 | 40
Steel Assembly | RIGID_FRAME | 612.6 | +13.990 | +14.030 | 1'-1/B-A' | A15 | 40
Steel Assembly | RIGID_FRAME | 306.3 | +13.990 | +14.030 | 1'-1/B-A' | A14 | 40
2 x Steel Assembly | RIGID_FRAME | 454.6 | +13.990 | +14.030 | 1-2/A'-A | A16 | 40
2 x Steel Assembly | RIGID_FRAME | 454.6 | +13.990 | +14.030 | 1'-2/B-A' | A16 | 40
3 x Steel Assembly | RIGID_FRAME | 612.6 | +13.990 | +14.030 | 1-2/B-A | A15 | 40
Steel Assembly | RIGID_FRAME | 612.6 | +13.990 | +14.030 | 1-2/A'-A | A15 | 40
Steel Assembly | RIGID_FRAME | 306.3 | +13.990 | +14.030 | 1-2/A'-A | A14 | 40
4 x Steel Assembly | RIGID_FRAME | 612.6 | +13.990 | +14.030 | 1'-1/D-C | A15 | 40
Steel Assembly | RIGID_FRAME | 306.3 | +13.990 | +14.030 | 1'-1/C | A14 | 40
2 x Steel Assembly | RIGID_FRAME | 454.6 | +13.990 | +14.030 | 1'-1/D-C | A16 | 40
Steel Assembly | RIGID_FRAME | 612.6 | +13.990 | +14.030 | 1'-1/D'-C | A15 | 40
Steel Assembly | RIGID_FRAME | 612.6 | +13.990 | +14.030 | 1'-1/D'-D | A15 | 40
Steel Assembly | RIGID_FRAME | 306.3 | +13.990 | +14.030 | 1'-1/D'-D | A14 | 40
2 x Steel Assembly | RIGID_FRAME | 454.6 | +13.990 | +14.030 | 1-2/E-D' | A16 | 40
2 x Steel Assembly | RIGID_FRAME | 454.6 | +13.990 | +14.030 | 1'-2/D'-D | A16 | 40
3 x Steel Assembly | RIGID_FRAME | 612.6 | +13.990 | +14.030 | 1-2/E-D | A15 | 40
Steel Assembly | RIGID_FRAME | 612.6 | +13.990 | +14.030 | 1-2/E-D' | A15 | 40
Steel Assembly | RIGID_FRAME | 306.3 | +13.990 | +14.030 | 1-2/E-D' | A14 | 40
Steel Assembly | RIGID_FRAME | 306.3 | +13.990 | +14.030 | 2-3/A'-A | A14 | 40
4 x Steel Assembly | RIGID_FRAME | 612.6 | +13.990 | +14.030 | 2-3/A'-A | A15 | 40
Steel Assembly | RIGID_FRAME | 306.3 | +13.990 | +14.030 | 2-3/E-D' | A14 | 40
4 x Steel Assembly | RIGID_FRAME | 612.6 | +13.990 | +14.030 | 2-3/E-D' | A15 | 40
3 x Steel Assembly | RIGID_FRAME | 0.9 | +13.880 | +13.984 | 1'-1/B-A' | B4 | 40
4 x Steel Assembly | RIGID_FRAME | 0.9 | +13.880 | +13.984 | 1'/C-B | B4 | 40
2 x Steel Assembly | RIGID_FRAME | 0.9 | +13.880 | +13.984 | 1'-1/C-B | B4 | 40
Steel Assembly | RIGID_FRAME | 0.9 | +13.880 | +13.984 | 1'-1/B | B4 | 40
Steel Assembly | RIGID_FRAME | 0.9 | +13.880 | +13.984 | 1'-1/A' | B4 | 40
Steel Assembly | RIGID_FRAME | 0.9 | +13.880 | +13.984 | 1-2/A | B4 | 40
4 x Steel Assembly | RIGID_FRAME | 0.9 | +13.880 | +13.984 | 1-2/A'-A | B4 | 40
Steel Assembly | RIGID_FRAME | 0.9 | +13.880 | +13.984 | 1/A' | B4 | 40
3 x Steel Assembly | RIGID_FRAME | 0.9 | +13.880 | +13.984 | 4-4'/B-A' | B4 | 40
Steel Assembly | RIGID_FRAME | 0.9 | +13.880 | +13.984 | 4'/C-B | B4 | 40
2 x Steel Assembly | RIGID_FRAME | 0.9 | +13.880 | +13.984 | 4-4'/C-B | B4 | 40
Steel Assembly | RIGID_FRAME | 0.9 | +13.880 | +13.984 | 4-4'/B | B4 | 40
Steel Assembly | RIGID_FRAME | 0.9 | +13.880 | +13.984 | 4-4'/A' | B4 | 40
Steel Assembly | RIGID_FRAME | 0.9 | +13.880 | +13.984 | 3-4/A | B4 | 40
4 x Steel Assembly | RIGID_FRAME | 0.9 | +13.880 | +13.984 | 3-4/A'-A | B4 | 40
Steel Assembly | RIGID_FRAME | 0.9 | +13.880 | +13.984 | 4/A' | B4 | 40
4 x Steel Assembly | RIGID_FRAME | 0.9 | +13.880 | +13.984 | 1'/D-C | B4 | 40
Steel Assembly | RIGID_FRAME | 0.9 | +13.880 | +13.984 | 1'/C | B4 | 40
3 x Steel Assembly | RIGID_FRAME | 0.9 | +13.880 | +13.984 | 4-4'/D'-D | B4 | 40
Steel Assembly | RIGID_FRAME | 0.9 | +13.880 | +13.984 | 4'/D-C | B4 | 40
2 x Steel Assembly | RIGID_FRAME | 0.9 | +13.880 | +13.984 | 4-4'/D-C | B4 | 40
Steel Assembly | RIGID_FRAME | 0.9 | +13.880 | +13.984 | 4-4'/D | B4 | 40
Steel Assembly | RIGID_FRAME | 0.9 | +13.880 | +13.984 | 4-4'/D' | B4 | 40
Steel Assembly | RIGID_FRAME | 0.9 | +13.880 | +13.984 | 3-4/E | B4 | 40
4 x Steel Assembly | RIGID_FRAME | 0.9 | +13.880 | +13.984 | 3-4/E-D' | B4 | 40
Steel Assembly | RIGID_FRAME | 0.9 | +13.880 | +13.984 | 4/D' | B4 | 40
3 x Steel Assembly | RIGID_FRAME | 0.9 | +13.880 | +13.984 | 1'-1/D'-D | B4 | 40
2 x Steel Assembly | RIGID_FRAME | 0.9 | +13.880 | +13.984 | 1'-1/D-C | B4 | 40
Steel Assembly | RIGID_FRAME | 0.9 | +13.880 | +13.984 | 1'-1/D | B4 | 40
Steel Assembly | RIGID_FRAME | 0.9 | +13.880 | +13.984 | 1'-1/D' | B4 | 40
Steel Assembly | RIGID_FRAME | 0.9 | +13.880 | +13.984 | 1-2/E | B4 | 40
4 x Steel Assembly | RIGID_FRAME | 0.9 | +13.880 | +13.984 | 1-2/E-D' | B4 | 40
Steel Assembly | RIGID_FRAME | 0.9 | +13.880 | +13.984 | 1/D' | B4 | 40
Steel Assembly | RIGID_FRAME | 0.9 | +13.880 | +13.984 | 3/A | B4 | 40
5 x Steel Assembly | RIGID_FRAME | 0.9 | +13.880 | +13.984 | 2-3/A | B4 | 40
Steel Assembly | RIGID_FRAME | 0.9 | +13.880 | +13.984 | 2/A | B4 | 40
Steel Assembly | RIGID_FRAME | 0.9 | +13.880 | +13.984 | 3/E | B4 | 40
5 x Steel Assembly | RIGID_FRAME | 0.9 | +13.880 | +13.984 | 2-3/E | B4 | 40
Steel Assembly | RIGID_FRAME | 0.9 | +13.880 | +13.984 | 2/E | B4 | 40
Steel Assembly | RIGID_FRAME | 607.3 | +13.940 | +14.024 | 3-4'/E-D' | B11 | 84
CONCRETE_SLAB | REINFORCEMENT_UNIT | 125051 | +13.880 | +14.030 | 1'-4'/E-A | P2 | 150 | Tekla Assembly - Cast unit type: Wylewany na miejscu; Cast unit rebar weight: 0 kg
Steel Assembly | RIGID_FRAME | 981.2 | +13.880 | +14.030 | 2-3/A'-A | B10 | 20568
3 x Steel Assembly | RIGID_FRAME | 54.4 | +13.700 | +13.880 | 4-4'/C-B | B6 | 91
3 x Steel Assembly | RIGID_FRAME | 54.4 | +13.700 | +13.880 | 4-4'/D-C | B6 | 91
Steel Assembly | RIGID_FRAME | 37.7 | +12.804 | +13.880 | 2-3/A'-A | B9 | 64
Steel Assembly | RIGID_FRAME | 37.7 | +12.804 | +13.880 | 2-3/E-D' | B9 | 64
Steel Assembly | RIGID_FRAME | 1.9 | +13.848 | +13.951 | 3-4/<E-D' | B5 | 10
Steel Assembly | RIGID_FRAME | 1.9 | +13.848 | +13.951 | 3-4/E | B5 | 10
Steel Assembly | RIGID_FRAME | 1.9 | +13.848 | +13.951 | 4'/D'-C | B5 | 10
Steel Assembly | RIGID_FRAME | 1.9 | +13.848 | +13.951 | 4-5/D-C | B5 | 10
Steel Assembly | RIGID_FRAME | 1.9 | +13.848 | +13.951 | 4-5/C-B | B5 | 10
Steel Assembly | RIGID_FRAME | 1.9 | +13.848 | +13.951 | 4'/C-A' | B5 | 10
Steel Assembly | RIGID_FRAME | 1.9 | +13.848 | +13.951 | 3-4/A | B5 | 10
Steel Assembly | RIGID_FRAME | 1.9 | +13.848 | +13.951 | 3-4/A'-A> | B5 | 10
Steel Assembly | RIGID_FRAME | 1.9 | +13.848 | +13.951 | 1-2/A'-A> | B5 | 10
Steel Assembly | RIGID_FRAME | 1.9 | +13.848 | +13.951 | 1-2/A | B5 | 10
Steel Assembly | RIGID_FRAME | 1.9 | +13.848 | +13.951 | 1'/C-A' | B5 | 10
Steel Assembly | RIGID_FRAME | 1.9 | +13.848 | +13.951 | <1'-1/C-B | B5 | 10
Steel Assembly | RIGID_FRAME | 1.9 | +13.848 | +13.951 | <1'-1/D-C | B5 | 10
Steel Assembly | RIGID_FRAME | 1.9 | +13.847 | +13.951 | 1'/D'-C | B5 | 10
Steel Assembly | RIGID_FRAME | 1.9 | +13.848 | +13.951 | 1-2/E | B5 | 10
Steel Assembly | RIGID_FRAME | 1.9 | +13.848 | +13.951 | 1-2/<E-D' | B5 | 10
2 x Steel Assembly | RIGID_FRAME | 54.4 | +13.700 | +13.880 | 1'-1/C-B | B6 | 91
2 x Steel Assembly | RIGID_FRAME | 54.4 | +13.700 | +13.880 | 1'-1/D-C | B6 | 91
3 x Steel Assembly | RIGID_FRAME | 60.2 | +13.700 | +13.880 | 1-2/B-A' | B7 | 91
6 x Steel Assembly | RIGID_FRAME | 54.4 | +13.700 | +13.880 | 1-2/C-B | B6 | 91
6 x Steel Assembly | RIGID_FRAME | 54.4 | +13.700 | +13.880 | 1-2/D-C | B6 | 91
3 x Steel Assembly | RIGID_FRAME | 60.2 | +13.700 | +13.880 | 3-4/B-A' | B7 | 91
6 x Steel Assembly | RIGID_FRAME | 54.4 | +13.700 | +13.880 | 3-4/C-B | B6 | 91
6 x Steel Assembly | RIGID_FRAME | 54.4 | +13.700 | +13.880 | 3-4/D-C | B6 | 91
3 x Steel Assembly | RIGID_FRAME | 60.2 | +13.700 | +13.880 | 1-2/D'-D | B7 | 91
3 x Steel Assembly | RIGID_FRAME | 60.2 | +13.700 | +13.880 | 3-4/D'-D | B7 | 91
2 x Steel Assembly | RIGID_FRAME | 28.5 | +13.760 | +13.880 | 2-3/E-D' | B8 | 64
2 x Steel Assembly | RIGID_FRAME | 28.5 | +13.760 | +13.880 | 2-3/A'-A | B8 | 64
3 x Steel Assembly | RIGID_FRAME | 60.2 | +13.700 | +13.880 | 2-3/B-A' | B7 | 91
6 x Steel Assembly | RIGID_FRAME | 54.4 | +13.700 | +13.880 | 2-3/C-B | B6 | 91
6 x Steel Assembly | RIGID_FRAME | 54.4 | +13.700 | +13.880 | 2-3/D-C | B6 | 91
3 x Steel Assembly | RIGID_FRAME | 60.2 | +13.700 | +13.880 | 2-3/D'-D | B7 | 91
Steel Assembly | RIGID_FRAME | 57.5 | +12.780 | +13.983 | 4'-5>/D-C | K5 | 973.948
Steel Assembly | RIGID_FRAME | 7.3 | +13.910 | +13.980 | 4-4'/E-D' | K10 | 420.577
Steel Assembly | RIGID_FRAME | 7.3 | +13.910 | +13.980 | 1'-1/E-D' | K10 | 466.211
Steel Assembly | RIGID_FRAME | 7.8 | +13.910 | +13.980 | <1'/D-C | K1 | 421.988
Steel Assembly | RIGID_FRAME | 6.9 | +13.910 | +13.980 | <1'/C-B | K4 | 421.988
Steel Assembly | RIGID_FRAME | 7.3 | +13.910 | +13.980 | 1'-1/A'-A | K10 | 466.168
Steel Assembly | RIGID_FRAME | 6.9 | +13.910 | +13.980 | 5>/C-B | K4 | 421.122
Steel Assembly | RIGID_FRAME | 7.3 | +13.910 | +13.980 | 4-4'/A'-A | K10 | 420.578
Steel Assembly | RIGID_FRAME | 13.2 | +13.910 | +13.980 | 3-4/<E | K6 | 40
Steel Assembly | RIGID_FRAME | 6.5 | +13.910 | +13.980 | 3-4/<E | K25 | 376.476
Steel Assembly | RIGID_FRAME | 6.5 | +13.910 | +13.980 | 1-2/<E | K25 | 421.062
Steel Assembly | RIGID_FRAME | 6.5 | +13.910 | +13.980 | 3-4/A> | K25 | 376.476
Steel Assembly | RIGID_FRAME | 6.5 | +13.910 | +13.980 | 1-2/A> | K25 | 421.062
Steel Assembly | RIGID_FRAME | 12.1 | +13.911 | +13.981 | 5>/C-B | K36 | 40
Steel Assembly | RIGID_FRAME | 13.2 | +13.910 | +13.980 | 3-4/A> | K6 | 40
Steel Assembly | RIGID_FRAME | 13.2 | +13.910 | +13.980 | 3-4'/A'-A | K6 | 40
Steel Assembly | RIGID_FRAME | 13.2 | +13.910 | +13.980 | 4-4'/B-A' | K6 | 40
Steel Assembly | RIGID_FRAME | 13.2 | +13.910 | +13.980 | 4'-5/C-A' | K6 | 40
2 x Steel Assembly | RIGID_FRAME | 13.2 | +13.910 | +13.980 | 2-3/A> | K6 | 40
Steel Assembly | RIGID_FRAME | 13.2 | +13.910 | +13.980 | 1-2/A> | K6 | 40
Steel Assembly | RIGID_FRAME | 13.2 | +13.910 | +13.980 | 1'-2/A'-A | K6 | 40
Steel Assembly | RIGID_FRAME | 13.2 | +13.910 | +13.980 | 1'-1/B-A' | K6 | 40
Steel Assembly | RIGID_FRAME | 13.2 | +13.910 | +13.980 | <1'/C-A' | K6 | 40
Steel Assembly | RIGID_FRAME | 6.9 | +13.910 | +13.980 | <1'/C-B | K3 | 40
Steel Assembly | RIGID_FRAME | 6.7 | +13.910 | +13.980 | <1'/C-B | K2 | 40
Steel Assembly | RIGID_FRAME | 13.2 | +13.910 | +13.980 | <1'/D'-C | K6 | 40
Steel Assembly | RIGID_FRAME | 13.2 | +13.910 | +13.980 | 1'-1/D'-D | K6 | 40
Steel Assembly | RIGID_FRAME | 13.2 | +13.910 | +13.980 | 1'-2/E-D' | K6 | 40
Steel Assembly | RIGID_FRAME | 13.2 | +13.910 | +13.980 | 1-2/<E | K6 | 40
Steel Assembly | RIGID_FRAME | 13.2 | +13.910 | +13.980 | 4'-5/D'-C | K6 | 40
Steel Assembly | RIGID_FRAME | 13.2 | +13.910 | +13.980 | 4-4'/D'-D | K6 | 40
Steel Assembly | RIGID_FRAME | 13.2 | +13.910 | +13.980 | 3-4'/E-D' | K6 | 40
2 x Steel Assembly | RIGID_FRAME | 13.2 | +13.910 | +13.980 | 2-3/<E | K6 | 40
Steel Assembly | RIGID_FRAME | 4 | +13.681 | +13.981 | 5>/C | K32 | 253.823
Steel Assembly | RIGID_FRAME | 24.1 | +12.780 | +13.966 | 4'-5/C | K33 | 973.948
2 x Steel Assembly | RIGID_FRAME | 27.9 | +12.780 | +13.980 | <1'/D-C | K31 | 973.948
Steel Assembly | RIGID_FRAME | 27.9 | +12.780 | +13.980 | <1'/C | K31 | 973.948
3 x Steel Assembly | RIGID_FRAME | 27.9 | +12.780 | +13.980 | <1'/C-B | K31 | 973.948
2 x Steel Assembly | RIGID_FRAME | 27.9 | +12.780 | +13.980 | 1'-1/D'-D | K31 | 973.948
Steel Assembly | RIGID_FRAME | 27.9 | +12.780 | +13.980 | 4'-5/D-C | K31 | 973.948
2 x Steel Assembly | RIGID_FRAME | 27.9 | +12.780 | +13.980 | 4-4'/D'-D | K31 | 973.948
Steel Assembly | RIGID_FRAME | 27.9 | +12.780 | +13.980 | 1'-1/E-D' | K31 | 973.948
Steel Assembly | RIGID_FRAME | 27.9 | +12.780 | +13.980 | 1-2/<E | K31 | 973.948
Steel Assembly | RIGID_FRAME | 27.9 | +12.780 | +13.980 | 1-2/E-D' | K31 | 973.948
Steel Assembly | RIGID_FRAME | 27.9 | +12.780 | +13.980 | 4-4'/E-D' | K31 | 973.948
Steel Assembly | RIGID_FRAME | 27.9 | +12.780 | +13.980 | 3-4/<E | K31 | 973.948
Steel Assembly | RIGID_FRAME | 27.9 | +12.780 | +13.980 | 3-4/E-D' | K31 | 973.948
2 x Steel Assembly | RIGID_FRAME | 27.9 | +12.780 | +13.980 | 1'-1/B-A' | K31 | 973.948
Steel Assembly | RIGID_FRAME | 27.9 | +12.780 | +13.980 | 4'-5/C-B | K31 | 973.948
2 x Steel Assembly | RIGID_FRAME | 27.9 | +12.780 | +13.980 | 4-4'/B-A' | K31 | 973.948
Steel Assembly | RIGID_FRAME | 27.9 | +12.780 | +13.980 | 1'-1/A'-A | K31 | 973.948
Steel Assembly | RIGID_FRAME | 27.9 | +12.780 | +13.980 | 1-2/A> | K31 | 973.948
Steel Assembly | RIGID_FRAME | 27.9 | +12.780 | +13.980 | 1-2/A'-A | K31 | 973.948
Steel Assembly | RIGID_FRAME | 27.9 | +12.780 | +13.980 | 4-4'/A'-A | K31 | 973.948
Steel Assembly | RIGID_FRAME | 27.9 | +12.780 | +13.980 | 3-4/A> | K31 | 973.948
Steel Assembly | RIGID_FRAME | 27.9 | +12.780 | +13.980 | 3-4/A'-A | K31 | 973.948
Steel Assembly | RIGID_FRAME | 27.9 | +12.780 | +13.980 | 4'-5>/C-B | K31 | 973.948
Steel Assembly | RIGID_FRAME | 27.9 | +12.780 | +13.980 | 2/<E | K31 | 973.948
Steel Assembly | RIGID_FRAME | 27.9 | +12.780 | +13.980 | 3/<E | K31 | 973.948
Steel Assembly | RIGID_FRAME | 27.9 | +12.780 | +13.980 | 2-3/<E | K31 | 973.948
Steel Assembly | RIGID_FRAME | 27.9 | +12.780 | +13.980 | 2/A> | K31 | 973.948
Steel Assembly | RIGID_FRAME | 27.9 | +12.780 | +13.980 | 3/A> | K31 | 973.948
Steel Assembly | RIGID_FRAME | 27.9 | +12.780 | +13.980 | 2-3/A> | K31 | 973.948
4 x Steel Assembly | RIGID_FRAME | 6.1 | +12.772 | +12.788 | 3-4/C-B | K21 | 16
4 x Steel Assembly | RIGID_FRAME | 6.1 | +12.772 | +12.788 | 2-3/C-B | K21 | 16
4 x Steel Assembly | RIGID_FRAME | 6.1 | +12.772 | +12.788 | 1-2/C-B | K21 | 16
4 x Steel Assembly | RIGID_FRAME | 6.1 | +12.772 | +12.788 | 1-2/D-C | K21 | 16
4 x Steel Assembly | RIGID_FRAME | 6.1 | +12.772 | +12.788 | 3-4/D-C | K21 | 16
4 x Steel Assembly | RIGID_FRAME | 6.1 | +12.772 | +12.788 | 2-3/D-C | K21 | 16
2 x Steel Assembly | RIGID_FRAME | 6.5 | +12.772 | +12.788 | 2-3/B-A' | K27 | 16
2 x Steel Assembly | RIGID_FRAME | 5.7 | +12.772 | +12.788 | 2-3/A'-A | K26 | 16
2 x Steel Assembly | RIGID_FRAME | 6.5 | +12.772 | +12.788 | 2-3/D'-D | K27 | 16
2 x Steel Assembly | RIGID_FRAME | 5.7 | +12.772 | +12.788 | 2-3/E-D' | K26 | 16
Steel Assembly | RIGID_FRAME | 323.8 | +7.491 | +13.880 | 4/B | S13 | 303.799
2 x Steel Assembly | RIGID_FRAME | 12.6 | +12.805 | +12.855 | 2-3/A'-A | K17 | 60
Steel Assembly | RIGID_FRAME | 1520.1 | +12.780 | +13.880 | 1-4/A | K30 | 6100.92
2 x Steel Assembly | RIGID_FRAME | 12.6 | +12.805 | +12.855 | 2-3/E-D' | K17 | 60
Steel Assembly | RIGID_FRAME | 1519.6 | +12.780 | +13.880 | 1-4/E | K28 | 6100.92
2 x Steel Assembly | RIGID_FRAME | 12.6 | +12.805 | +12.855 | 4-4'/D-C | K17 | 60
Steel Assembly | RIGID_FRAME | 177 | +12.780 | +13.880 | 4-4'/D | K16 | 1100
Steel Assembly | RIGID_FRAME | 381.4 | +12.780 | +13.880 | 4/D-C | K20 | 1100
4 x Steel Assembly | RIGID_FRAME | 12.6 | +12.805 | +12.855 | 3-4/D-C | K17 | 60
Steel Assembly | RIGID_FRAME | 346.7 | +12.780 | +13.880 | 3-4/D | K23 | 1100
Steel Assembly | RIGID_FRAME | 381.4 | +12.780 | +13.880 | 3/D-C | K20 | 1100
4 x Steel Assembly | RIGID_FRAME | 12.6 | +12.805 | +12.855 | 2-3/D-C | K17 | 60
Steel Assembly | RIGID_FRAME | 346.7 | +12.780 | +13.880 | 2-3/D | K23 | 1100
Steel Assembly | RIGID_FRAME | 381.4 | +12.780 | +13.880 | 2/D-C | K20 | 1100
4 x Steel Assembly | RIGID_FRAME | 12.6 | +12.805 | +12.855 | 1-2/D-C | K17 | 60
Steel Assembly | RIGID_FRAME | 346.7 | +12.780 | +13.880 | 1-2/D | K23 | 1100
Steel Assembly | RIGID_FRAME | 381.4 | +12.780 | +13.880 | 1/D-C | K20 | 1100
2 x Steel Assembly | RIGID_FRAME | 12.6 | +12.805 | +12.855 | 1'-1/D-C | K17 | 60
Steel Assembly | RIGID_FRAME | 177 | +12.780 | +13.880 | 1'-1/D | K15 | 1100
4 x Steel Assembly | RIGID_FRAME | 12.6 | +12.805 | +12.855 | 1-2/C-B | K17 | 60
Steel Assembly | RIGID_FRAME | 346.7 | +12.780 | +13.880 | 1-2/B | K23 | 1100
Steel Assembly | RIGID_FRAME | 381.4 | +12.780 | +13.880 | 1/C-B | K20 | 1100
2 x Steel Assembly | RIGID_FRAME | 12.6 | +12.805 | +12.855 | 1'-1/C-B | K17 | 60
Steel Assembly | RIGID_FRAME | 177 | +12.780 | +13.880 | 1'-1/B | K16 | 1100
4 x Steel Assembly | RIGID_FRAME | 12.6 | +12.805 | +12.855 | 2-3/C-B | K17 | 60
Steel Assembly | RIGID_FRAME | 346.7 | +12.780 | +13.880 | 2-3/B | K23 | 1100
Steel Assembly | RIGID_FRAME | 381.4 | +12.780 | +13.880 | 2/C-B | K20 | 1100
2 x Steel Assembly | RIGID_FRAME | 12.6 | +12.805 | +12.855 | 4-4'/C-B | K17 | 60
Steel Assembly | RIGID_FRAME | 177 | +12.780 | +13.880 | 4-4'/B | K15 | 1100
Steel Assembly | RIGID_FRAME | 381.4 | +12.780 | +13.880 | 4/C-B | K20 | 1100
4 x Steel Assembly | RIGID_FRAME | 12.6 | +12.805 | +12.855 | 3-4/C-B | K17 | 60
Steel Assembly | RIGID_FRAME | 346.7 | +12.780 | +13.880 | 3-4/B | K23 | 1100
Steel Assembly | RIGID_FRAME | 280.8 | +12.780 | +13.880 | 4-4'/C | K12 | 1100
Steel Assembly | RIGID_FRAME | 347.8 | +12.780 | +13.880 | 3-4/C | K24 | 1100
Steel Assembly | RIGID_FRAME | 347.8 | +12.780 | +13.880 | 1-2/C | K24 | 1100
Steel Assembly | RIGID_FRAME | 280.8 | +12.780 | +13.880 | 1'-1/C | K12 | 1100
Steel Assembly | RIGID_FRAME | 347.8 | +12.780 | +13.880 | 2-3/C | K24 | 1100
Steel Assembly | RIGID_FRAME | 381.4 | +12.780 | +13.880 | 3/C-B | K20 | 1100
Steel Assembly | RIGID_FRAME | 165.4 | +12.780 | +13.880 | 4'/C-B | K9 | 1100
Steel Assembly | RIGID_FRAME | 165.4 | +12.780 | +13.880 | 4'/D-C | K9 | 1100
Steel Assembly | RIGID_FRAME | 165.4 | +12.780 | +13.880 | 1'/C-B | K9 | 1100
Steel Assembly | RIGID_FRAME | 165.4 | +12.780 | +13.880 | 1'/D-C | K9 | 1100
Steel Assembly | RIGID_FRAME | 186 | +12.780 | +13.880 | 4'/C-B | K7 | 1100
Steel Assembly | RIGID_FRAME | 186 | +12.780 | +13.880 | 1'/C-B | K8 | 1100
Steel Assembly | RIGID_FRAME | 186 | +12.780 | +13.880 | 4'/D-C | K8 | 1100
Steel Assembly | RIGID_FRAME | 186 | +12.780 | +13.880 | 1'/D-C | K7 | 1100
Steel Assembly | RIGID_FRAME | 190.3 | +12.780 | +13.880 | 1'-1/D'-D | K13 | 498.108
Steel Assembly | RIGID_FRAME | 190.3 | +12.780 | +13.880 | 4-4'/D'-D | K14 | 498.108
Steel Assembly | RIGID_FRAME | 190.3 | +12.780 | +13.880 | 1'-1/B-A' | K14 | 498.108
Steel Assembly | RIGID_FRAME | 190.3 | +12.780 | +13.880 | 4-4'/B-A' | K13 | 498.108
Steel Assembly | RIGID_FRAME | 281.2 | +12.780 | +13.880 | 1'-1/C-B | K11 | 1100
Steel Assembly | RIGID_FRAME | 281.2 | +12.780 | +13.880 | 1'-1/D-C | K11 | 1100
Steel Assembly | RIGID_FRAME | 281.2 | +12.780 | +13.880 | 4-4'/C-B | K11 | 1100
Steel Assembly | RIGID_FRAME | 281.2 | +12.780 | +13.880 | 4-4'/D-C | K11 | 1100
Steel Assembly | RIGID_FRAME | 348.5 | +12.780 | +13.880 | 3-4/A' | K22 | 1100
Steel Assembly | RIGID_FRAME | 348.5 | +12.780 | +13.880 | 1-2/A' | K22 | 1100
Steel Assembly | RIGID_FRAME | 348.5 | +12.780 | +13.880 | 1-2/D' | K22 | 1100
Steel Assembly | RIGID_FRAME | 348.5 | +12.780 | +13.880 | 3-4/D' | K22 | 1100
Steel Assembly | RIGID_FRAME | 221.9 | +12.780 | +13.880 | 1/B-A' | K19 | 1100
Steel Assembly | RIGID_FRAME | 221.9 | +12.780 | +13.880 | 4/B-A' | K19 | 1100
Steel Assembly | RIGID_FRAME | 221.9 | +12.780 | +13.880 | 1/D'-D | K19 | 1100
Steel Assembly | RIGID_FRAME | 221.9 | +12.780 | +13.880 | 4/D'-D | K19 | 1100
Steel Assembly | RIGID_FRAME | 348.5 | +12.780 | +13.880 | 2-3/A' | K22 | 1100
Steel Assembly | RIGID_FRAME | 348.5 | +12.780 | +13.880 | 2-3/D' | K22 | 1100
Steel Assembly | RIGID_FRAME | 348.5 | +12.780 | +13.880 | 3-4/C-B | K22 | 1100
Steel Assembly | RIGID_FRAME | 348.5 | +12.780 | +13.880 | 2-3/C-B | K22 | 1100
Steel Assembly | RIGID_FRAME | 348.5 | +12.780 | +13.880 | 1-2/C-B | K22 | 1100
Steel Assembly | RIGID_FRAME | 348.5 | +12.780 | +13.880 | 3-4/D-C | K22 | 1100
Steel Assembly | RIGID_FRAME | 348.5 | +12.780 | +13.880 | 2-3/D-C | K22 | 1100
Steel Assembly | RIGID_FRAME | 348.5 | +12.780 | +13.880 | 1-2/D-C | K22 | 1100
Steel Assembly | RIGID_FRAME | 321.9 | +7.491 | +13.880 | 4/D | S12 | 177.8
Steel Assembly | RIGID_FRAME | 321.9 | +7.491 | +13.880 | 1/D | S12 | 177.8
Steel Assembly |  | 0 | +7.271 | +7.481 | 1'-4/E-A> | P1 | 210

# IfcMechanicalFastener: Bolt assembly (571)
In: Undefined
Material: Undefined
Tekla Bolt - Slotted hole y: 0 mm; Location: Budowa; Bolt Name: SRUBA
Name | NominalDiameter (mm) = Washer diameter (mm) = Bolt size (mm) | NominalLength (mm) = Bolt length (mm) | Washer count | Washer type | Washer name | Nut count = Bolt count | Nut type | Nut name | Slotted hole x (mm) | Bolt hole diameter (mm) | Bolt standard
32 x Bolt assembly | 16 | 45 | 4 | 7089 | PODKLADKA-16-7089 | 2 | 4032 | NAKRETKA-M16-4032 | 0 | 19 | 4017
36 x Bolt assembly | 16 | 40 | 4 | 7089 | PODKLADKA-16-7089 | 2 | 4032 | NAKRETKA-M16-4032 | 0 | 19 | 4017
107 x Bolt assembly | 16 | 40 | 4 | 7089 | PODKLADKA-16-7089 | 2 | 4032 | NAKRETKA-M16-4032 | 0 | 18 | 4017
32 x Bolt assembly | 16 | 45 | 4 | 7089 | PODKLADKA-16-7089 | 2 | 4032 | NAKRETKA-M16-4032 | 0 | 18 | 4017
146 x Bolt assembly | 12 | 35 | 2 | 125A | PODKLADKA-12-125A | 1 | 934 | NAKRETKA-M12-934 | 20 | 15 | 931
146 x Bolt assembly | 12 | 35 | 2 | 125A | PODKLADKA-12-125A | 1 | 934 | NAKRETKA-M12-934 | 0 | 15 | 931
72 x Bolt assembly | 12 | 35 | 4 | 7089 | PODKLADKA-12-7089 | 2 | 4032 | NAKRETKA-M12-4032 | 0 | 13 | 4017

# IfcMember: CHS60.3*6.3 (21)
In: Undefined
Description: CHS60.3*6.3; Material: STEEL/S235
Tekla Common - Phase: 4; Class: 5
Tekla Quantity - Volume: 0 m3; Gross footprint area: 0 m2; Area per tons: 23.1 m2; Height: 60.3 mm; Width: 60.3 mm
Pset_MemberCommon - LoadBearing: no
BaseQuantities - CrossSectionArea: 0.00104151 m2
Name | Bottom elevation | Top elevation | Weight (kg) | Net surface area (m2) | Tekla Quantity, Length (mm) | Reference | BaseQuantities, Length (mm) | OuterSurfaceArea (m2) | GrossSurfaceArea (m2) | NetVolume (m3) | GrossVolume (m3) | NetWeight (kg) | GrossWeight (kg)
3 x BEAM | +7.765 | +10.045 | 28.5 | 0.8 | 3497.1 | xx5 | 3497.1 | 0.658984 | 0.659398 | 0.00363219 | 0.00364227 | 28.5127 | 28.5918
3 x BEAM | +7.765 | +12.467 | 59.5 | 1.4 | 7287.1 | xx6 | 7287.1 | 1.37235 | 1.37276 | 0.00757952 | 0.0075896 | 59.4992 | 59.5783
3 x BEAM | +10.187 | +12.467 | 28.5 | 0.8 | 3497.1 | xx5 | 3497.1 | 0.658983 | 0.659398 | 0.00363219 | 0.00364227 | 28.5127 | 28.5918
4 x BEAM | +7.781 | +10.041 | 26.6 | 0.6 | 3267 | xx1 | 3266.98 | 0.615669 | 0.616084 | 0.00339252 | 0.0034026 | 26.6312 | 26.7104
4 x BEAM | +7.781 | +12.451 | 55.7 | 1.3 | 6818.4 | xx2 | 6818.4 | 1.28413 | 1.28454 | 0.00709136 | 0.00710144 | 55.6671 | 55.7463
4 x BEAM | +10.191 | +12.451 | 26.6 | 0.6 | 3267 | xx1 | 3266.98 | 0.61567 | 0.616085 | 0.00339252 | 0.0034026 | 26.6313 | 26.7104

# IfcMember: CHS76.1*3 (36)
In: Undefined
Description: CHS76.1*3; Material: STEEL/S235JR
Tekla Common - Phase: 4; Class: 2
Tekla Quantity - Volume: 0 m3; Gross footprint area: 0 m2; Area per tons: 45.2 m2; Net surface area: 0.8 m2; Height: 76.1 mm; Width: 76.1 mm
Pset_MemberCommon - LoadBearing: no
BaseQuantities - CrossSectionArea: 0.00067138 m2
Name | Bottom elevation | Top elevation | Weight (kg) | Tekla Quantity, Length (mm) | Reference | BaseQuantities, Length (mm) | OuterSurfaceArea (m2) | GrossSurfaceArea (m2) | NetVolume (m3) | GrossVolume (m3) | NetWeight (kg) | GrossWeight (kg)
5 x BEAM | +7.782 | +9.988 | 16.6 | 3169.8 | s1 | 3169.77 | 0.751226 | 0.753654 | 0.0021184 | 0.00212812 | 16.6295 | 16.7058
5 x BEAM | +7.782 | +9.988 | 16.6 | 3169.8 | s1 | 3169.77 | 0.751225 | 0.753653 | 0.0021184 | 0.00212812 | 16.6294 | 16.7057
5 x BEAM | +10.244 | +12.450 | 16.6 | 3169.8 | s1 | 3169.77 | 0.751225 | 0.753653 | 0.0021184 | 0.00212812 | 16.6294 | 16.7057
5 x BEAM | +10.244 | +12.450 | 16.6 | 3169.8 | s1 | 3169.77 | 0.751226 | 0.753654 | 0.0021184 | 0.00212812 | 16.6295 | 16.7058
4 x BEAM | +10.240 | +12.467 | 17.8 | 3395.7 | s3 | 3395.69 | 0.804891 | 0.807318 | 0.00227008 | 0.0022798 | 17.8201 | 17.8964
4 x BEAM | +7.765 | +9.992 | 17.8 | 3395.7 | s3 | 3395.69 | 0.804891 | 0.807318 | 0.00227008 | 0.0022798 | 17.8201 | 17.8964
4 x BEAM | +7.765 | +9.992 | 17.8 | 3395.7 | s3 | 3395.69 | 0.80489 | 0.807317 | 0.00227008 | 0.0022798 | 17.8201 | 17.8964
4 x BEAM | +10.240 | +12.467 | 17.8 | 3395.7 | s3 | 3395.69 | 0.80489 | 0.807317 | 0.00227008 | 0.0022798 | 17.8201 | 17.8964

# IfcMember: SHS50*4 (38)
In: Undefined
Description: SHS50*4; Material: STEEL/S235
Tekla Common - Phase: 4; Class: 11
Tekla Quantity - Volume: 0 m3; Gross footprint area: 0 m2; Width: 50 mm
Pset_MemberCommon - LoadBearing: no
BaseQuantities - CrossSectionArea: 0.00069095 m2
Name | Bottom elevation | Top elevation | Weight (kg) | Area per tons (m2) | Net surface area (m2) | Height (mm) | Tekla Quantity, Length (mm) | Reference | BaseQuantities, Length (mm) | OuterSurfaceArea (m2) | GrossSurfaceArea (m2) | NetVolume (m3) | GrossVolume (m3) | NetWeight (kg) | GrossWeight (kg)
BEAM | +13.681 | +13.861 | 1.7 | 35.1 | 0.1 | 50.1 | 329.4 | k63 | 329.42 | 0.0605045 | 0.458359 | 0.000219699 | 0.00168332 | 1.72464 | 13.2141
BEAM | +12.780 | +13.737 | 11.2 | 34.7 | 0.4 | 50 | 1964.5 | k61 | 1964.45 | 0.387805 | 0.452592 | 0.00142378 | 0.00166259 | 11.1767 | 13.0514
36 x BEAM | +12.780 | +13.860 | 12.9 | 34.7 | 0.4 | 50 | 2259 | k56 | 2258.96 | 0.447064 | 0.449637 | 0.00164181 | 0.00165147 | 12.8882 | 12.9641

# IfcMember: UPN200 (14)
In: Undefined
Description: UPN200; Material: STEEL/S235
Tekla Common - Phase: 2; Class: 3
Tekla Quantity - Volume: 0 m3; Gross footprint area: 0 m2; Area per tons: 26.1 m2; Height: 200 mm; Width: 75 mm
Pset_MemberCommon - LoadBearing: yes
BaseQuantities - CrossSectionArea: 0.00322 m2
Name | Bottom elevation | Top elevation | Weight (kg) | Net surface area (m2) | Tekla Quantity, Length (mm) | Reference | BaseQuantities, Length (mm) | OuterSurfaceArea (m2) = GrossSurfaceArea (m2) | NetVolume (m3) | GrossVolume (m3) | NetWeight (kg) | GrossWeight (kg)
BELKA | +12.150 | +14.000 | 94.5 | 2.4 | 3736.7 | k116 | 3736.73 | 2.46624 | 0.0119153 | 0.0120323 | 93.5349 | 94.4532
BELKA | +12.150 | +14.000 | 94.5 | 2.4 | 3736.7 | k115 | 3736.73 | 2.46624 | 0.0119153 | 0.0120323 | 93.5349 | 94.4532
BELKA | +10.500 | +12.350 | 94.5 | 2.4 | 3736.7 | k116 | 3736.73 | 2.46624 | 0.0119153 | 0.0120323 | 93.5349 | 94.4532
BELKA | +10.500 | +12.350 | 94.5 | 2.4 | 3736.7 | k115 | 3736.73 | 2.46624 | 0.0119153 | 0.0120323 | 93.5349 | 94.4532
BELKA | +8.850 | +10.700 | 94.5 | 2.4 | 3736.7 | k116 | 3736.73 | 2.46624 | 0.0119153 | 0.0120323 | 93.5349 | 94.4532
BELKA | +8.850 | +10.700 | 94.5 | 2.4 | 3736.7 | k115 | 3736.73 | 2.46624 | 0.0119153 | 0.0120323 | 93.5349 | 94.4532
BELKA | +7.200 | +9.050 | 94.5 | 2.4 | 3736.7 | k116 | 3736.73 | 2.46624 | 0.0119153 | 0.0120323 | 93.5349 | 94.4532
BELKA | +7.200 | +9.050 | 94.5 | 2.4 | 3736.7 | k115 | 3736.73 | 2.46624 | 0.0119153 | 0.0120323 | 93.5349 | 94.4532
BELKA | +5.550 | +7.400 | 94.5 | 2.4 | 3736.7 | k116 | 3736.73 | 2.46624 | 0.0119153 | 0.0120323 | 93.5349 | 94.4532
BELKA | +5.550 | +7.400 | 94.5 | 2.4 | 3736.7 | k115 | 3736.73 | 2.46624 | 0.0119153 | 0.0120323 | 93.5349 | 94.4532
BELKA | +3.900 | +5.750 | 94.5 | 2.4 | 3736.7 | k116 | 3736.73 | 2.46624 | 0.0119153 | 0.0120323 | 93.5349 | 94.4532
BELKA | +3.900 | +5.750 | 94.5 | 2.4 | 3736.7 | k115 | 3736.73 | 2.46624 | 0.0119153 | 0.0120323 | 93.5349 | 94.4532
BELKA | +2.780 | +4.100 | 64.4 | 1.7 | 2551.6 | k110 | 2551.61 | 1.68406 | 0.00808795 | 0.00821618 | 63.4904 | 64.497
BELKA | +2.780 | +4.100 | 64.4 | 1.7 | 2551.6 | k109 | 2551.61 | 1.68406 | 0.00808795 | 0.00821618 | 63.4904 | 64.497

# IfcPlate: 210*17200, CONCRETE_SLAB
In: Undefined
Description: 210*17200; Material: MISCELLANEOUS/DUMMY
Pset_PlateCommon - LoadBearing: yes; Reference: P1
Tekla Common - Bottom elevation: +7.271; Top elevation: +7.481; Phase: 4; Class: 1
Tekla Quantity - Weight: 0 kg; Volume: 88.4 m3; Gross footprint area: 421 m2; Area per tons: 0 m2; Net surface area: 859 m2; Height: 17200 mm; Width: 210 mm; Length: 25000 mm
BaseQuantities - Width: 17200 mm; NetArea: 858.986 m2; GrossArea: 430 m2; CrossSectionArea: 0.0441 m2; NetVolume: 88.41 m3; GrossVolume: 88.41 m3

# IfcPlate: BL2*1000 (44)
In: Undefined
Description: BL2*1000; Material: STEEL/S235
Tekla Common - Bottom elevation: +14.030; Top elevation: +14.032; Phase: 4; Class: 3
Tekla Quantity - Weight: 32.8 kg; Volume: 0 m3; Gross footprint area: 2 m2; Area per tons: 119.2 m2; Net surface area: 3.9 m2; Height: 1000 mm; Width: 2 mm; Length: 1951 mm
Pset_PlateCommon - LoadBearing: no; Reference: A18
BaseQuantities - Width: 1000 mm; NetArea: 3.9138 m2; GrossArea: 1.951 m2; CrossSectionArea: 0.000004 m2; NetVolume: 0.003902 m3; GrossVolume: 0.003902 m3

# IfcPlate: BL2*1002 (20)
In: Undefined
Description: BL2*1002; Material: STEEL/S235
Tekla Common - Bottom elevation: +14.030; Top elevation: +14.032; Phase: 4; Class: 3
Tekla Quantity - Weight: 24.4 kg; Volume: 0 m3; Gross footprint area: 1.4 m2; Area per tons: 119.3 m2; Net surface area: 2.9 m2; Height: 1002.5 mm; Width: 2 mm; Length: 1951 mm
Pset_PlateCommon - LoadBearing: no
BaseQuantities - Width: 1002.49 mm; NetArea: 2.90623 m2; GrossArea: 1.95575 m2; CrossSectionArea: 0.000004 m2; NetVolume: 0.00289532 m3; GrossVolume: 0.00289532 m3
Name | Reference
10 x BLACHA RYFLOWANA | A19
10 x BLACHA RYFLOWANA | A20

# IfcPlate: BL2*1461 (2)
In: Undefined
Description: BL2*1461; Material: STEEL/S235
Tekla Common - Bottom elevation: +14.030; Top elevation: +14.032; Phase: 4; Class: 3
Tekla Quantity - Weight: 36.8 kg; Volume: 0 m3; Gross footprint area: 2.2 m2; Area per tons: 119.2 m2; Net surface area: 4.4 m2; Height: 1460.9 mm; Width: 2 mm; Length: 2442.6 mm
Pset_PlateCommon - LoadBearing: no
BaseQuantities - Width: 1460.93 mm; NetArea: 4.3833 m2; GrossArea: 3.56848 m2; CrossSectionArea: 0.000004 m2; NetVolume: 0.00437063 m3; GrossVolume: 0.00437063 m3
Name | Reference
BLACHA RYFLOWANA | A23
BLACHA RYFLOWANA | A22

# IfcPlate: BL2*500 (9)
In: Undefined
Description: BL2*500; Material: STEEL/S235
Tekla Common - Bottom elevation: +14.030; Top elevation: +14.032; Phase: 4; Class: 3
Tekla Quantity - Weight: 16.4 kg; Volume: 0 m3; Gross footprint area: 1 m2; Area per tons: 119.3 m2; Net surface area: 2 m2; Height: 500 mm; Width: 2 mm; Length: 1951 mm
Pset_PlateCommon - LoadBearing: no; Reference: A12
BaseQuantities - Width: 500 mm; NetArea: 1.9608 m2; GrossArea: 0.9755 m2; CrossSectionArea: 0.000004 m2; NetVolume: 0.001951 m3; GrossVolume: 0.001951 m3

# IfcPlate: BL30*1500 (3)
In: Undefined
Description: BL30*1500; Material: STEEL/S235
Tekla Common - Phase: 2; Class: 2
Tekla Quantity - Weight: 1077.4 kg; Volume: 0.1 m3; Gross footprint area: 4.6 m2; Area per tons: 8.7 m2; Net surface area: 9.4 m2; Height: 1500 mm; Width: 30 mm; Length: 3050 mm
Pset_PlateCommon - LoadBearing: no; Reference: A2
BaseQuantities - Width: 1500 mm; NetArea: 9.423 m2; GrossArea: 4.575 m2; CrossSectionArea: 0.0009 m2; NetVolume: 0.13725 m3; GrossVolume: 0.13725 m3
Name | Bottom elevation | Top elevation
KRATA | +12.350 | +12.380
KRATA | +9.050 | +9.080
KRATA | +5.750 | +5.780

# IfcPlate: BL30*1875 (3)
In: Undefined
Description: BL30*1875; Material: STEEL/S235
Tekla Common - Phase: 2; Class: 2
Tekla Quantity - Weight: 1346.8 kg; Volume: 0.2 m3; Gross footprint area: 5.7 m2; Area per tons: 8.7 m2; Net surface area: 11.7 m2; Height: 1875 mm; Width: 30 mm; Length: 3050 mm
Pset_PlateCommon - LoadBearing: no
BaseQuantities - Width: 1875 mm; NetArea: 11.733 m2; GrossArea: 5.71875 m2; CrossSectionArea: 0.0009 m2; NetVolume: 0.171563 m3; GrossVolume: 0.171563 m3
Name | Bottom elevation | Top elevation | Reference
KRATA | +10.700 | +10.730 | SCH3
KRATA | +7.400 | +7.430 | A13
KRATA | +4.100 | +4.130 | A13

# IfcPlate: BL30*750, KRATA
In: Undefined
Description: BL30*750; Material: STEEL/S235
Tekla Common - Bottom elevation: +14.000; Top elevation: +14.030; Phase: 2; Class: 2
Tekla Quantity - Weight: 247.3 kg; Volume: 0 m3; Gross footprint area: 1.1 m2; Area per tons: 9 m2; Net surface area: 2.2 m2; Height: 750 mm; Width: 30 mm; Length: 1400 mm
Pset_PlateCommon - LoadBearing: no; Reference: SCH2
BaseQuantities - Width: 750 mm; NetArea: 2.229 m2; GrossArea: 1.05 m2; CrossSectionArea: 0.0009 m2; NetVolume: 0.0315 m3; GrossVolume: 0.0315 m3

# IfcPlate: BL40*1000 (44)
In: Undefined
Description: BL40*1000; Material: STEEL/S235
Tekla Common - Bottom elevation: +13.990; Top elevation: +14.030; Phase: 4; Class: 1
Tekla Quantity - Weight: 612.6 kg; Volume: 0.1 m3; Gross footprint area: 2 m2; Area per tons: 6.8 m2; Net surface area: 4.2 m2; Height: 1000 mm; Width: 40 mm; Length: 1951 mm
Pset_PlateCommon - LoadBearing: no; Reference: A15
BaseQuantities - Width: 1000 mm; NetArea: 4.13808 m2; GrossArea: 1.951 m2; CrossSectionArea: 0.0016 m2; NetVolume: 0.07804 m3; GrossVolume: 0.07804 m3

# IfcPlate: BL40*1002 (20)
In: Undefined
Description: BL40*1002; Material: STEEL/S235
Tekla Common - Bottom elevation: +13.990; Top elevation: +14.030; Phase: 4; Class: 1
Tekla Quantity - Weight: 454.6 kg; Volume: 0.1 m3; Gross footprint area: 1.4 m2; Area per tons: 6.8 m2; Net surface area: 3.1 m2; Height: 1002.5 mm; Width: 40 mm; Length: 1951 mm
Pset_PlateCommon - LoadBearing: no; Reference: A16
BaseQuantities - Width: 1002.49 mm; NetArea: 3.11349 m2; GrossArea: 1.95575 m2; CrossSectionArea: 0.0016 m2; NetVolume: 0.0579065 m3; GrossVolume: 0.0579065 m3

# IfcPlate: BL40*1461 (2)
In: Undefined
Description: BL40*1461; Material: STEEL/S235
Tekla Common - Bottom elevation: +13.990; Top elevation: +14.030; Phase: 4; Class: 1
Tekla Quantity - Weight: 686.2 kg; Volume: 0.1 m3; Gross footprint area: 2.2 m2; Area per tons: 6.7 m2; Net surface area: 4.6 m2; Height: 1460.9 mm; Width: 40 mm; Length: 2442.6 mm
Pset_PlateCommon - LoadBearing: no; Reference: A17
BaseQuantities - Width: 1460.93 mm; NetArea: 4.62409 m2; GrossArea: 3.56848 m2; CrossSectionArea: 0.0016 m2; NetVolume: 0.0874125 m3; GrossVolume: 0.0874125 m3

# IfcPlate: BL40*500 (9)
In: Undefined
Description: BL40*500; Material: STEEL/S235
Tekla Common - Bottom elevation: +13.990; Top elevation: +14.030; Phase: 4; Class: 1
Tekla Quantity - Weight: 306.3 kg; Volume: 0 m3; Gross footprint area: 1 m2; Area per tons: 7 m2; Net surface area: 2.1 m2; Height: 500 mm; Width: 40 mm; Length: 1951 mm
Pset_PlateCommon - LoadBearing: no; Reference: A14
BaseQuantities - Width: 500 mm; NetArea: 2.14708 m2; GrossArea: 0.9755 m2; CrossSectionArea: 0.0016 m2; NetVolume: 0.03902 m3; GrossVolume: 0.03902 m3

# IfcSlab: 150*22384, CONCRETE_SLAB
In: Undefined
Description: 150*22384; PredefinedType: FLOOR; Material: CONCRETE/C25/30
Tekla Common - Bottom elevation: +13.880; Top elevation: +14.030; Phase: 4; Class: 1
Tekla Quantity - Weight: 125051 kg; Volume: 52.1 m3; Gross footprint area: 347.4 m2; Area per tons: 5.6 m2; Net surface area: 705.2 m2; Height: 22384 mm; Width: 150 mm; Length: 20418 mm
Pset_SlabCommon - LoadBearing: yes; Reference: P2
BaseQuantities - Width: 150 mm; NetVolume: 52.1045 m3; NetArea: 347.364 m2; NetWeight: 125051 kg
